VERSION 5.7 ;
  NOWIREEXTENSIONATPIN ON ;
  DIVIDERCHAR "/" ;
  BUSBITCHARS "[]" ;
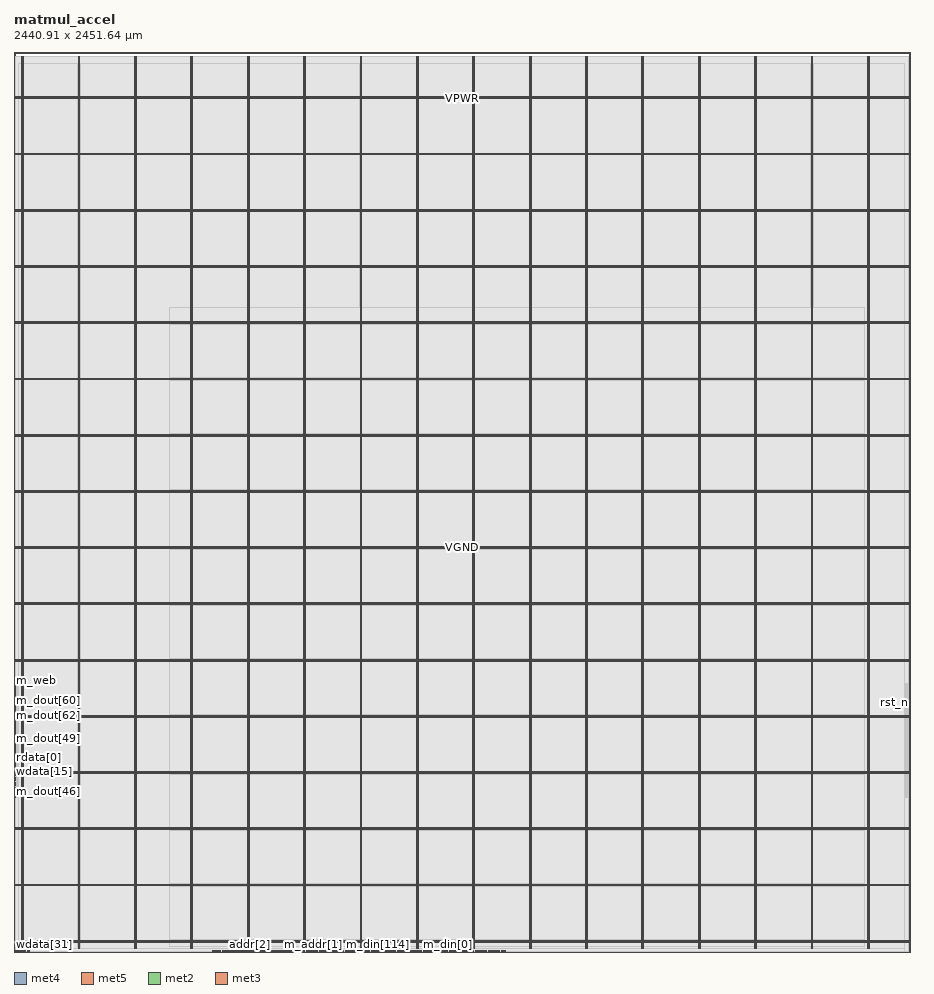
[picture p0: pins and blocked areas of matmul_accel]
MACRO matmul_accel
  CLASS BLOCK ;
  FOREIGN matmul_accel ;
  ORIGIN 0.000 0.000 ;
  SIZE 2440.915 BY 2451.635 ;
  PIN VGND
    DIRECTION INOUT ;
    USE GROUND ;
    PORT
      LAYER met4 ;
        RECT 24.340 10.640 25.940 2440.080 ;
    END
    PORT
      LAYER met4 ;
        RECT 177.940 10.640 179.540 2440.080 ;
    END
    PORT
      LAYER met4 ;
        RECT 331.540 10.640 333.140 2440.080 ;
    END
    PORT
      LAYER met4 ;
        RECT 485.140 10.640 486.740 2440.080 ;
    END
    PORT
      LAYER met4 ;
        RECT 638.740 10.640 640.340 2440.080 ;
    END
    PORT
      LAYER met4 ;
        RECT 792.340 10.640 793.940 2440.080 ;
    END
    PORT
      LAYER met4 ;
        RECT 945.940 10.640 947.540 2440.080 ;
    END
    PORT
      LAYER met4 ;
        RECT 1099.540 10.640 1101.140 2440.080 ;
    END
    PORT
      LAYER met4 ;
        RECT 1253.140 10.640 1254.740 2440.080 ;
    END
    PORT
      LAYER met4 ;
        RECT 1406.740 10.640 1408.340 2440.080 ;
    END
    PORT
      LAYER met4 ;
        RECT 1560.340 10.640 1561.940 2440.080 ;
    END
    PORT
      LAYER met4 ;
        RECT 1713.940 10.640 1715.540 2440.080 ;
    END
    PORT
      LAYER met4 ;
        RECT 1867.540 10.640 1869.140 2440.080 ;
    END
    PORT
      LAYER met4 ;
        RECT 2021.140 10.640 2022.740 2440.080 ;
    END
    PORT
      LAYER met4 ;
        RECT 2174.740 10.640 2176.340 2440.080 ;
    END
    PORT
      LAYER met4 ;
        RECT 2328.340 10.640 2329.940 2440.080 ;
    END
    PORT
      LAYER met5 ;
        RECT 5.280 30.030 2435.480 31.630 ;
    END
    PORT
      LAYER met5 ;
        RECT 5.280 183.210 2435.480 184.810 ;
    END
    PORT
      LAYER met5 ;
        RECT 5.280 336.390 2435.480 337.990 ;
    END
    PORT
      LAYER met5 ;
        RECT 5.280 489.570 2435.480 491.170 ;
    END
    PORT
      LAYER met5 ;
        RECT 5.280 642.750 2435.480 644.350 ;
    END
    PORT
      LAYER met5 ;
        RECT 5.280 795.930 2435.480 797.530 ;
    END
    PORT
      LAYER met5 ;
        RECT 5.280 949.110 2435.480 950.710 ;
    END
    PORT
      LAYER met5 ;
        RECT 5.280 1102.290 2435.480 1103.890 ;
    END
    PORT
      LAYER met5 ;
        RECT 5.280 1255.470 2435.480 1257.070 ;
    END
    PORT
      LAYER met5 ;
        RECT 5.280 1408.650 2435.480 1410.250 ;
    END
    PORT
      LAYER met5 ;
        RECT 5.280 1561.830 2435.480 1563.430 ;
    END
    PORT
      LAYER met5 ;
        RECT 5.280 1715.010 2435.480 1716.610 ;
    END
    PORT
      LAYER met5 ;
        RECT 5.280 1868.190 2435.480 1869.790 ;
    END
    PORT
      LAYER met5 ;
        RECT 5.280 2021.370 2435.480 2022.970 ;
    END
    PORT
      LAYER met5 ;
        RECT 5.280 2174.550 2435.480 2176.150 ;
    END
    PORT
      LAYER met5 ;
        RECT 5.280 2327.730 2435.480 2329.330 ;
    END
  END VGND
  PIN VPWR
    DIRECTION INOUT ;
    USE POWER ;
    PORT
      LAYER met4 ;
        RECT 21.040 10.640 22.640 2440.080 ;
    END
    PORT
      LAYER met4 ;
        RECT 174.640 10.640 176.240 2440.080 ;
    END
    PORT
      LAYER met4 ;
        RECT 328.240 10.640 329.840 2440.080 ;
    END
    PORT
      LAYER met4 ;
        RECT 481.840 10.640 483.440 2440.080 ;
    END
    PORT
      LAYER met4 ;
        RECT 635.440 10.640 637.040 2440.080 ;
    END
    PORT
      LAYER met4 ;
        RECT 789.040 10.640 790.640 2440.080 ;
    END
    PORT
      LAYER met4 ;
        RECT 942.640 10.640 944.240 2440.080 ;
    END
    PORT
      LAYER met4 ;
        RECT 1096.240 10.640 1097.840 2440.080 ;
    END
    PORT
      LAYER met4 ;
        RECT 1249.840 10.640 1251.440 2440.080 ;
    END
    PORT
      LAYER met4 ;
        RECT 1403.440 10.640 1405.040 2440.080 ;
    END
    PORT
      LAYER met4 ;
        RECT 1557.040 10.640 1558.640 2440.080 ;
    END
    PORT
      LAYER met4 ;
        RECT 1710.640 10.640 1712.240 2440.080 ;
    END
    PORT
      LAYER met4 ;
        RECT 1864.240 10.640 1865.840 2440.080 ;
    END
    PORT
      LAYER met4 ;
        RECT 2017.840 10.640 2019.440 2440.080 ;
    END
    PORT
      LAYER met4 ;
        RECT 2171.440 10.640 2173.040 2440.080 ;
    END
    PORT
      LAYER met4 ;
        RECT 2325.040 10.640 2326.640 2440.080 ;
    END
    PORT
      LAYER met5 ;
        RECT 5.280 26.730 2435.480 28.330 ;
    END
    PORT
      LAYER met5 ;
        RECT 5.280 179.910 2435.480 181.510 ;
    END
    PORT
      LAYER met5 ;
        RECT 5.280 333.090 2435.480 334.690 ;
    END
    PORT
      LAYER met5 ;
        RECT 5.280 486.270 2435.480 487.870 ;
    END
    PORT
      LAYER met5 ;
        RECT 5.280 639.450 2435.480 641.050 ;
    END
    PORT
      LAYER met5 ;
        RECT 5.280 792.630 2435.480 794.230 ;
    END
    PORT
      LAYER met5 ;
        RECT 5.280 945.810 2435.480 947.410 ;
    END
    PORT
      LAYER met5 ;
        RECT 5.280 1098.990 2435.480 1100.590 ;
    END
    PORT
      LAYER met5 ;
        RECT 5.280 1252.170 2435.480 1253.770 ;
    END
    PORT
      LAYER met5 ;
        RECT 5.280 1405.350 2435.480 1406.950 ;
    END
    PORT
      LAYER met5 ;
        RECT 5.280 1558.530 2435.480 1560.130 ;
    END
    PORT
      LAYER met5 ;
        RECT 5.280 1711.710 2435.480 1713.310 ;
    END
    PORT
      LAYER met5 ;
        RECT 5.280 1864.890 2435.480 1866.490 ;
    END
    PORT
      LAYER met5 ;
        RECT 5.280 2018.070 2435.480 2019.670 ;
    END
    PORT
      LAYER met5 ;
        RECT 5.280 2171.250 2435.480 2172.850 ;
    END
    PORT
      LAYER met5 ;
        RECT 5.280 2324.430 2435.480 2326.030 ;
    END
  END VPWR
  PIN addr[0]
    DIRECTION INPUT ;
    USE SIGNAL ;
    PORT
      LAYER met2 ;
        RECT 0.090 0.000 0.370 4.000 ;
    END
  END addr[0]
  PIN addr[10]
    DIRECTION INPUT ;
    USE SIGNAL ;
    ANTENNAGATEAREA 0.929700 ;
    ANTENNADIFFAREA 0.434700 ;
    PORT
      LAYER met2 ;
        RECT 676.290 0.000 676.570 4.000 ;
    END
  END addr[10]
  PIN addr[11]
    DIRECTION INPUT ;
    USE SIGNAL ;
    ANTENNAGATEAREA 0.860700 ;
    ANTENNADIFFAREA 0.434700 ;
    PORT
      LAYER met3 ;
        RECT 0.000 731.040 4.000 731.640 ;
    END
  END addr[11]
  PIN addr[12]
    DIRECTION INPUT ;
    USE SIGNAL ;
    ANTENNAGATEAREA 0.860700 ;
    ANTENNADIFFAREA 0.434700 ;
    PORT
      LAYER met3 ;
        RECT 0.000 669.840 4.000 670.440 ;
    END
  END addr[12]
  PIN addr[1]
    DIRECTION INPUT ;
    USE SIGNAL ;
    PORT
      LAYER met2 ;
        RECT 3.310 0.000 3.590 4.000 ;
    END
  END addr[1]
  PIN addr[2]
    DIRECTION INPUT ;
    USE SIGNAL ;
    ANTENNAGATEAREA 0.860700 ;
    ANTENNADIFFAREA 0.434700 ;
    PORT
      LAYER met2 ;
        RECT 644.090 0.000 644.370 4.000 ;
    END
  END addr[2]
  PIN addr[3]
    DIRECTION INPUT ;
    USE SIGNAL ;
    ANTENNAGATEAREA 0.860700 ;
    ANTENNADIFFAREA 0.434700 ;
    PORT
      LAYER met2 ;
        RECT 682.730 0.000 683.010 4.000 ;
    END
  END addr[3]
  PIN addr[4]
    DIRECTION INPUT ;
    USE SIGNAL ;
    ANTENNAGATEAREA 0.682200 ;
    ANTENNADIFFAREA 0.434700 ;
    PORT
      LAYER met2 ;
        RECT 673.070 0.000 673.350 4.000 ;
    END
  END addr[4]
  PIN addr[5]
    DIRECTION INPUT ;
    USE SIGNAL ;
    ANTENNAGATEAREA 0.682200 ;
    ANTENNADIFFAREA 0.434700 ;
    PORT
      LAYER met2 ;
        RECT 663.410 0.000 663.690 4.000 ;
    END
  END addr[5]
  PIN addr[6]
    DIRECTION INPUT ;
    USE SIGNAL ;
    ANTENNAGATEAREA 0.860700 ;
    ANTENNADIFFAREA 0.434700 ;
    PORT
      LAYER met3 ;
        RECT 0.000 663.040 4.000 663.640 ;
    END
  END addr[6]
  PIN addr[7]
    DIRECTION INPUT ;
    USE SIGNAL ;
    ANTENNAGATEAREA 0.682200 ;
    ANTENNADIFFAREA 0.434700 ;
    PORT
      LAYER met3 ;
        RECT 0.000 656.240 4.000 656.840 ;
    END
  END addr[7]
  PIN addr[8]
    DIRECTION INPUT ;
    USE SIGNAL ;
    ANTENNAGATEAREA 0.860700 ;
    ANTENNADIFFAREA 0.434700 ;
    PORT
      LAYER met3 ;
        RECT 0.000 659.640 4.000 660.240 ;
    END
  END addr[8]
  PIN addr[9]
    DIRECTION INPUT ;
    USE SIGNAL ;
    ANTENNAGATEAREA 0.860700 ;
    ANTENNADIFFAREA 0.434700 ;
    PORT
      LAYER met3 ;
        RECT 0.000 601.840 4.000 602.440 ;
    END
  END addr[9]
  PIN busy
    DIRECTION OUTPUT ;
    USE SIGNAL ;
    ANTENNADIFFAREA 0.445500 ;
    PORT
      LAYER met2 ;
        RECT 708.490 0.000 708.770 4.000 ;
    END
  END busy
  PIN clk
    DIRECTION INPUT ;
    USE SIGNAL ;
    ANTENNAGATEAREA 1.286700 ;
    ANTENNADIFFAREA 0.434700 ;
    PORT
      LAYER met2 ;
        RECT 25.850 0.000 26.130 4.000 ;
    END
  END clk
  PIN done
    DIRECTION OUTPUT ;
    USE SIGNAL ;
    ANTENNADIFFAREA 0.445500 ;
    PORT
      LAYER met2 ;
        RECT 711.710 0.000 711.990 4.000 ;
    END
  END done
  PIN m_addr[0]
    DIRECTION OUTPUT ;
    USE SIGNAL ;
    ANTENNADIFFAREA 0.445500 ;
    PORT
      LAYER met2 ;
        RECT 782.550 0.000 782.830 4.000 ;
    END
  END m_addr[0]
  PIN m_addr[10]
    DIRECTION OUTPUT ;
    USE SIGNAL ;
    ANTENNADIFFAREA 0.445500 ;
    PORT
      LAYER met2 ;
        RECT 756.790 0.000 757.070 4.000 ;
    END
  END m_addr[10]
  PIN m_addr[11]
    DIRECTION OUTPUT ;
    USE SIGNAL ;
    ANTENNADIFFAREA 0.445500 ;
    PORT
      LAYER met2 ;
        RECT 750.350 0.000 750.630 4.000 ;
    END
  END m_addr[11]
  PIN m_addr[12]
    DIRECTION OUTPUT ;
    USE SIGNAL ;
    ANTENNADIFFAREA 0.445500 ;
    PORT
      LAYER met2 ;
        RECT 763.230 0.000 763.510 4.000 ;
    END
  END m_addr[12]
  PIN m_addr[13]
    DIRECTION OUTPUT ;
    USE SIGNAL ;
    ANTENNADIFFAREA 0.445500 ;
    PORT
      LAYER met2 ;
        RECT 760.010 0.000 760.290 4.000 ;
    END
  END m_addr[13]
  PIN m_addr[1]
    DIRECTION OUTPUT ;
    USE SIGNAL ;
    ANTENNADIFFAREA 0.445500 ;
    PORT
      LAYER met2 ;
        RECT 814.750 0.000 815.030 4.000 ;
    END
  END m_addr[1]
  PIN m_addr[2]
    DIRECTION OUTPUT ;
    USE SIGNAL ;
    ANTENNADIFFAREA 0.445500 ;
    PORT
      LAYER met2 ;
        RECT 817.970 0.000 818.250 4.000 ;
    END
  END m_addr[2]
  PIN m_addr[3]
    DIRECTION OUTPUT ;
    USE SIGNAL ;
    ANTENNADIFFAREA 0.445500 ;
    PORT
      LAYER met2 ;
        RECT 811.530 0.000 811.810 4.000 ;
    END
  END m_addr[3]
  PIN m_addr[4]
    DIRECTION OUTPUT ;
    USE SIGNAL ;
    ANTENNADIFFAREA 0.445500 ;
    PORT
      LAYER met2 ;
        RECT 753.570 0.000 753.850 4.000 ;
    END
  END m_addr[4]
  PIN m_addr[5]
    DIRECTION OUTPUT ;
    USE SIGNAL ;
    ANTENNADIFFAREA 0.445500 ;
    PORT
      LAYER met2 ;
        RECT 801.870 0.000 802.150 4.000 ;
    END
  END m_addr[5]
  PIN m_addr[6]
    DIRECTION OUTPUT ;
    USE SIGNAL ;
    ANTENNADIFFAREA 0.445500 ;
    PORT
      LAYER met2 ;
        RECT 766.450 0.000 766.730 4.000 ;
    END
  END m_addr[6]
  PIN m_addr[7]
    DIRECTION OUTPUT ;
    USE SIGNAL ;
    ANTENNADIFFAREA 0.445500 ;
    PORT
      LAYER met2 ;
        RECT 747.130 0.000 747.410 4.000 ;
    END
  END m_addr[7]
  PIN m_addr[8]
    DIRECTION OUTPUT ;
    USE SIGNAL ;
    ANTENNADIFFAREA 0.445500 ;
    PORT
      LAYER met2 ;
        RECT 740.690 0.000 740.970 4.000 ;
    END
  END m_addr[8]
  PIN m_addr[9]
    DIRECTION OUTPUT ;
    USE SIGNAL ;
    ANTENNADIFFAREA 0.445500 ;
    PORT
      LAYER met2 ;
        RECT 772.890 0.000 773.170 4.000 ;
    END
  END m_addr[9]
  PIN m_csb
    DIRECTION OUTPUT ;
    USE SIGNAL ;
    ANTENNADIFFAREA 0.445500 ;
    PORT
      LAYER met2 ;
        RECT 724.590 0.000 724.870 4.000 ;
    END
  END m_csb
  PIN m_din[0]
    DIRECTION OUTPUT ;
    USE SIGNAL ;
    ANTENNADIFFAREA 0.445500 ;
    PORT
      LAYER met2 ;
        RECT 1181.830 0.000 1182.110 4.000 ;
    END
  END m_din[0]
  PIN m_din[100]
    DIRECTION OUTPUT ;
    USE SIGNAL ;
    ANTENNADIFFAREA 0.445500 ;
    PORT
      LAYER met2 ;
        RECT 859.830 0.000 860.110 4.000 ;
    END
  END m_din[100]
  PIN m_din[101]
    DIRECTION OUTPUT ;
    USE SIGNAL ;
    ANTENNADIFFAREA 0.445500 ;
    PORT
      LAYER met2 ;
        RECT 1175.390 0.000 1175.670 4.000 ;
    END
  END m_din[101]
  PIN m_din[102]
    DIRECTION OUTPUT ;
    USE SIGNAL ;
    ANTENNADIFFAREA 0.445500 ;
    PORT
      LAYER met2 ;
        RECT 863.050 0.000 863.330 4.000 ;
    END
  END m_din[102]
  PIN m_din[103]
    DIRECTION OUTPUT ;
    USE SIGNAL ;
    ANTENNADIFFAREA 0.445500 ;
    PORT
      LAYER met2 ;
        RECT 1024.050 0.000 1024.330 4.000 ;
    END
  END m_din[103]
  PIN m_din[104]
    DIRECTION OUTPUT ;
    USE SIGNAL ;
    ANTENNADIFFAREA 0.445500 ;
    PORT
      LAYER met2 ;
        RECT 689.170 0.000 689.450 4.000 ;
    END
  END m_din[104]
  PIN m_din[105]
    DIRECTION OUTPUT ;
    USE SIGNAL ;
    ANTENNADIFFAREA 0.445500 ;
    PORT
      LAYER met2 ;
        RECT 1130.310 0.000 1130.590 4.000 ;
    END
  END m_din[105]
  PIN m_din[106]
    DIRECTION OUTPUT ;
    USE SIGNAL ;
    ANTENNADIFFAREA 0.445500 ;
    PORT
      LAYER met2 ;
        RECT 731.030 0.000 731.310 4.000 ;
    END
  END m_din[106]
  PIN m_din[107]
    DIRECTION OUTPUT ;
    USE SIGNAL ;
    ANTENNADIFFAREA 0.445500 ;
    PORT
      LAYER met2 ;
        RECT 743.910 0.000 744.190 4.000 ;
    END
  END m_din[107]
  PIN m_din[108]
    DIRECTION OUTPUT ;
    USE SIGNAL ;
    ANTENNADIFFAREA 0.445500 ;
    PORT
      LAYER met2 ;
        RECT 1236.570 0.000 1236.850 4.000 ;
    END
  END m_din[108]
  PIN m_din[109]
    DIRECTION OUTPUT ;
    USE SIGNAL ;
    ANTENNADIFFAREA 0.445500 ;
    PORT
      LAYER met2 ;
        RECT 830.850 0.000 831.130 4.000 ;
    END
  END m_din[109]
  PIN m_din[10]
    DIRECTION OUTPUT ;
    USE SIGNAL ;
    ANTENNADIFFAREA 0.445500 ;
    PORT
      LAYER met2 ;
        RECT 714.930 0.000 715.210 4.000 ;
    END
  END m_din[10]
  PIN m_din[110]
    DIRECTION OUTPUT ;
    USE SIGNAL ;
    ANTENNADIFFAREA 0.445500 ;
    PORT
      LAYER met2 ;
        RECT 882.370 0.000 882.650 4.000 ;
    END
  END m_din[110]
  PIN m_din[111]
    DIRECTION OUTPUT ;
    USE SIGNAL ;
    ANTENNADIFFAREA 0.445500 ;
    PORT
      LAYER met2 ;
        RECT 779.330 0.000 779.610 4.000 ;
    END
  END m_din[111]
  PIN m_din[112]
    DIRECTION OUTPUT ;
    USE SIGNAL ;
    ANTENNADIFFAREA 0.445500 ;
    PORT
      LAYER met2 ;
        RECT 647.310 0.000 647.590 4.000 ;
    END
  END m_din[112]
  PIN m_din[113]
    DIRECTION OUTPUT ;
    USE SIGNAL ;
    ANTENNADIFFAREA 0.445500 ;
    PORT
      LAYER met2 ;
        RECT 914.570 0.000 914.850 4.000 ;
    END
  END m_din[113]
  PIN m_din[114]
    DIRECTION OUTPUT ;
    USE SIGNAL ;
    ANTENNADIFFAREA 0.445500 ;
    PORT
      LAYER met2 ;
        RECT 991.850 0.000 992.130 4.000 ;
    END
  END m_din[114]
  PIN m_din[115]
    DIRECTION OUTPUT ;
    USE SIGNAL ;
    ANTENNADIFFAREA 0.445500 ;
    PORT
      LAYER met2 ;
        RECT 669.850 0.000 670.130 4.000 ;
    END
  END m_din[115]
  PIN m_din[116]
    DIRECTION OUTPUT ;
    USE SIGNAL ;
    ANTENNADIFFAREA 0.445500 ;
    PORT
      LAYER met2 ;
        RECT 718.150 0.000 718.430 4.000 ;
    END
  END m_din[116]
  PIN m_din[117]
    DIRECTION OUTPUT ;
    USE SIGNAL ;
    ANTENNADIFFAREA 0.445500 ;
    PORT
      LAYER met2 ;
        RECT 888.810 0.000 889.090 4.000 ;
    END
  END m_din[117]
  PIN m_din[118]
    DIRECTION OUTPUT ;
    USE SIGNAL ;
    ANTENNADIFFAREA 0.445500 ;
    PORT
      LAYER met2 ;
        RECT 1281.650 0.000 1281.930 4.000 ;
    END
  END m_din[118]
  PIN m_din[119]
    DIRECTION OUTPUT ;
    USE SIGNAL ;
    ANTENNADIFFAREA 0.445500 ;
    PORT
      LAYER met2 ;
        RECT 792.210 0.000 792.490 4.000 ;
    END
  END m_din[119]
  PIN m_din[11]
    DIRECTION OUTPUT ;
    USE SIGNAL ;
    ANTENNADIFFAREA 0.445500 ;
    PORT
      LAYER met2 ;
        RECT 885.590 0.000 885.870 4.000 ;
    END
  END m_din[11]
  PIN m_din[120]
    DIRECTION OUTPUT ;
    USE SIGNAL ;
    ANTENNADIFFAREA 0.445500 ;
    PORT
      LAYER met2 ;
        RECT 927.450 0.000 927.730 4.000 ;
    END
  END m_din[120]
  PIN m_din[121]
    DIRECTION OUTPUT ;
    USE SIGNAL ;
    ANTENNADIFFAREA 0.445500 ;
    PORT
      LAYER met2 ;
        RECT 666.630 0.000 666.910 4.000 ;
    END
  END m_din[121]
  PIN m_din[122]
    DIRECTION OUTPUT ;
    USE SIGNAL ;
    ANTENNADIFFAREA 0.445500 ;
    PORT
      LAYER met2 ;
        RECT 679.510 0.000 679.790 4.000 ;
    END
  END m_din[122]
  PIN m_din[123]
    DIRECTION OUTPUT ;
    USE SIGNAL ;
    ANTENNADIFFAREA 0.445500 ;
    PORT
      LAYER met2 ;
        RECT 1117.430 0.000 1117.710 4.000 ;
    END
  END m_din[123]
  PIN m_din[124]
    DIRECTION OUTPUT ;
    USE SIGNAL ;
    ANTENNADIFFAREA 0.445500 ;
    PORT
      LAYER met2 ;
        RECT 695.610 0.000 695.890 4.000 ;
    END
  END m_din[124]
  PIN m_din[125]
    DIRECTION OUTPUT ;
    USE SIGNAL ;
    ANTENNADIFFAREA 0.445500 ;
    PORT
      LAYER met2 ;
        RECT 901.690 0.000 901.970 4.000 ;
    END
  END m_din[125]
  PIN m_din[126]
    DIRECTION OUTPUT ;
    USE SIGNAL ;
    ANTENNADIFFAREA 0.445500 ;
    PORT
      LAYER met2 ;
        RECT 1014.390 0.000 1014.670 4.000 ;
    END
  END m_din[126]
  PIN m_din[127]
    DIRECTION OUTPUT ;
    USE SIGNAL ;
    ANTENNADIFFAREA 0.445500 ;
    PORT
      LAYER met2 ;
        RECT 1127.090 0.000 1127.370 4.000 ;
    END
  END m_din[127]
  PIN m_din[12]
    DIRECTION OUTPUT ;
    USE SIGNAL ;
    ANTENNADIFFAREA 0.445500 ;
    PORT
      LAYER met2 ;
        RECT 1133.530 0.000 1133.810 4.000 ;
    END
  END m_din[12]
  PIN m_din[13]
    DIRECTION OUTPUT ;
    USE SIGNAL ;
    ANTENNADIFFAREA 0.445500 ;
    PORT
      LAYER met2 ;
        RECT 834.070 0.000 834.350 4.000 ;
    END
  END m_din[13]
  PIN m_din[14]
    DIRECTION OUTPUT ;
    USE SIGNAL ;
    ANTENNADIFFAREA 0.445500 ;
    PORT
      LAYER met2 ;
        RECT 1252.670 0.000 1252.950 4.000 ;
    END
  END m_din[14]
  PIN m_din[15]
    DIRECTION OUTPUT ;
    USE SIGNAL ;
    ANTENNADIFFAREA 0.445500 ;
    PORT
      LAYER met2 ;
        RECT 1275.210 0.000 1275.490 4.000 ;
    END
  END m_din[15]
  PIN m_din[16]
    DIRECTION OUTPUT ;
    USE SIGNAL ;
    ANTENNADIFFAREA 0.445500 ;
    PORT
      LAYER met2 ;
        RECT 940.330 0.000 940.610 4.000 ;
    END
  END m_din[16]
  PIN m_din[17]
    DIRECTION OUTPUT ;
    USE SIGNAL ;
    ANTENNADIFFAREA 0.445500 ;
    PORT
      LAYER met2 ;
        RECT 1123.870 0.000 1124.150 4.000 ;
    END
  END m_din[17]
  PIN m_din[18]
    DIRECTION OUTPUT ;
    USE SIGNAL ;
    ANTENNADIFFAREA 0.445500 ;
    PORT
      LAYER met2 ;
        RECT 1065.910 0.000 1066.190 4.000 ;
    END
  END m_din[18]
  PIN m_din[19]
    DIRECTION OUTPUT ;
    USE SIGNAL ;
    ANTENNADIFFAREA 0.445500 ;
    PORT
      LAYER met2 ;
        RECT 1143.190 0.000 1143.470 4.000 ;
    END
  END m_din[19]
  PIN m_din[1]
    DIRECTION OUTPUT ;
    USE SIGNAL ;
    ANTENNADIFFAREA 0.445500 ;
    PORT
      LAYER met2 ;
        RECT 1059.470 0.000 1059.750 4.000 ;
    END
  END m_din[1]
  PIN m_din[20]
    DIRECTION OUTPUT ;
    USE SIGNAL ;
    ANTENNADIFFAREA 0.445500 ;
    PORT
      LAYER met2 ;
        RECT 1053.030 0.000 1053.310 4.000 ;
    END
  END m_din[20]
  PIN m_din[21]
    DIRECTION OUTPUT ;
    USE SIGNAL ;
    ANTENNADIFFAREA 0.445500 ;
    PORT
      LAYER met2 ;
        RECT 1259.110 0.000 1259.390 4.000 ;
    END
  END m_din[21]
  PIN m_din[22]
    DIRECTION OUTPUT ;
    USE SIGNAL ;
    ANTENNADIFFAREA 0.445500 ;
    PORT
      LAYER met2 ;
        RECT 1056.250 0.000 1056.530 4.000 ;
    END
  END m_din[22]
  PIN m_din[23]
    DIRECTION OUTPUT ;
    USE SIGNAL ;
    ANTENNADIFFAREA 0.445500 ;
    PORT
      LAYER met2 ;
        RECT 1156.070 0.000 1156.350 4.000 ;
    END
  END m_din[23]
  PIN m_din[24]
    DIRECTION OUTPUT ;
    USE SIGNAL ;
    ANTENNADIFFAREA 0.445500 ;
    PORT
      LAYER met2 ;
        RECT 1220.470 0.000 1220.750 4.000 ;
    END
  END m_din[24]
  PIN m_din[25]
    DIRECTION OUTPUT ;
    USE SIGNAL ;
    ANTENNADIFFAREA 0.445500 ;
    PORT
      LAYER met2 ;
        RECT 1001.510 0.000 1001.790 4.000 ;
    END
  END m_din[25]
  PIN m_din[26]
    DIRECTION OUTPUT ;
    USE SIGNAL ;
    ANTENNADIFFAREA 0.445500 ;
    PORT
      LAYER met2 ;
        RECT 1110.990 0.000 1111.270 4.000 ;
    END
  END m_din[26]
  PIN m_din[27]
    DIRECTION OUTPUT ;
    USE SIGNAL ;
    ANTENNADIFFAREA 0.445500 ;
    PORT
      LAYER met2 ;
        RECT 1239.790 0.000 1240.070 4.000 ;
    END
  END m_din[27]
  PIN m_din[28]
    DIRECTION OUTPUT ;
    USE SIGNAL ;
    ANTENNADIFFAREA 0.445500 ;
    PORT
      LAYER met2 ;
        RECT 1217.250 0.000 1217.530 4.000 ;
    END
  END m_din[28]
  PIN m_din[29]
    DIRECTION OUTPUT ;
    USE SIGNAL ;
    ANTENNADIFFAREA 0.445500 ;
    PORT
      LAYER met2 ;
        RECT 1207.590 0.000 1207.870 4.000 ;
    END
  END m_din[29]
  PIN m_din[2]
    DIRECTION OUTPUT ;
    USE SIGNAL ;
    ANTENNADIFFAREA 0.445500 ;
    PORT
      LAYER met2 ;
        RECT 1094.890 0.000 1095.170 4.000 ;
    END
  END m_din[2]
  PIN m_din[30]
    DIRECTION OUTPUT ;
    USE SIGNAL ;
    ANTENNADIFFAREA 0.445500 ;
    PORT
      LAYER met2 ;
        RECT 1004.730 0.000 1005.010 4.000 ;
    END
  END m_din[30]
  PIN m_din[31]
    DIRECTION OUTPUT ;
    USE SIGNAL ;
    ANTENNADIFFAREA 0.445500 ;
    PORT
      LAYER met2 ;
        RECT 1246.230 0.000 1246.510 4.000 ;
    END
  END m_din[31]
  PIN m_din[32]
    DIRECTION OUTPUT ;
    USE SIGNAL ;
    ANTENNADIFFAREA 0.445500 ;
    PORT
      LAYER met2 ;
        RECT 962.870 0.000 963.150 4.000 ;
    END
  END m_din[32]
  PIN m_din[33]
    DIRECTION OUTPUT ;
    USE SIGNAL ;
    ANTENNADIFFAREA 0.445500 ;
    PORT
      LAYER met2 ;
        RECT 1017.610 0.000 1017.890 4.000 ;
    END
  END m_din[33]
  PIN m_din[34]
    DIRECTION OUTPUT ;
    USE SIGNAL ;
    ANTENNADIFFAREA 0.445500 ;
    PORT
      LAYER met2 ;
        RECT 1036.930 0.000 1037.210 4.000 ;
    END
  END m_din[34]
  PIN m_din[35]
    DIRECTION OUTPUT ;
    USE SIGNAL ;
    ANTENNADIFFAREA 0.445500 ;
    PORT
      LAYER met2 ;
        RECT 1168.950 0.000 1169.230 4.000 ;
    END
  END m_din[35]
  PIN m_din[36]
    DIRECTION OUTPUT ;
    USE SIGNAL ;
    ANTENNADIFFAREA 0.445500 ;
    PORT
      LAYER met2 ;
        RECT 856.610 0.000 856.890 4.000 ;
    END
  END m_din[36]
  PIN m_din[37]
    DIRECTION OUTPUT ;
    USE SIGNAL ;
    ANTENNADIFFAREA 0.445500 ;
    PORT
      LAYER met2 ;
        RECT 1159.290 0.000 1159.570 4.000 ;
    END
  END m_din[37]
  PIN m_din[38]
    DIRECTION OUTPUT ;
    USE SIGNAL ;
    ANTENNADIFFAREA 0.445500 ;
    PORT
      LAYER met2 ;
        RECT 837.290 0.000 837.570 4.000 ;
    END
  END m_din[38]
  PIN m_din[39]
    DIRECTION OUTPUT ;
    USE SIGNAL ;
    ANTENNADIFFAREA 0.445500 ;
    PORT
      LAYER met2 ;
        RECT 978.970 0.000 979.250 4.000 ;
    END
  END m_din[39]
  PIN m_din[3]
    DIRECTION OUTPUT ;
    USE SIGNAL ;
    ANTENNADIFFAREA 0.445500 ;
    PORT
      LAYER met2 ;
        RECT 953.210 0.000 953.490 4.000 ;
    END
  END m_din[3]
  PIN m_din[40]
    DIRECTION OUTPUT ;
    USE SIGNAL ;
    ANTENNADIFFAREA 0.445500 ;
    PORT
      LAYER met2 ;
        RECT 769.670 0.000 769.950 4.000 ;
    END
  END m_din[40]
  PIN m_din[41]
    DIRECTION OUTPUT ;
    USE SIGNAL ;
    ANTENNADIFFAREA 0.445500 ;
    PORT
      LAYER met2 ;
        RECT 1107.770 0.000 1108.050 4.000 ;
    END
  END m_din[41]
  PIN m_din[42]
    DIRECTION OUTPUT ;
    USE SIGNAL ;
    ANTENNADIFFAREA 0.445500 ;
    PORT
      LAYER met2 ;
        RECT 776.110 0.000 776.390 4.000 ;
    END
  END m_din[42]
  PIN m_din[43]
    DIRECTION OUTPUT ;
    USE SIGNAL ;
    ANTENNADIFFAREA 0.445500 ;
    PORT
      LAYER met2 ;
        RECT 685.950 0.000 686.230 4.000 ;
    END
  END m_din[43]
  PIN m_din[44]
    DIRECTION OUTPUT ;
    USE SIGNAL ;
    ANTENNADIFFAREA 0.445500 ;
    PORT
      LAYER met2 ;
        RECT 1197.930 0.000 1198.210 4.000 ;
    END
  END m_din[44]
  PIN m_din[45]
    DIRECTION OUTPUT ;
    USE SIGNAL ;
    ANTENNADIFFAREA 0.445500 ;
    PORT
      LAYER met2 ;
        RECT 827.630 0.000 827.910 4.000 ;
    END
  END m_din[45]
  PIN m_din[46]
    DIRECTION OUTPUT ;
    USE SIGNAL ;
    ANTENNADIFFAREA 0.445500 ;
    PORT
      LAYER met2 ;
        RECT 805.090 0.000 805.370 4.000 ;
    END
  END m_din[46]
  PIN m_din[47]
    DIRECTION OUTPUT ;
    USE SIGNAL ;
    ANTENNADIFFAREA 0.445500 ;
    PORT
      LAYER met2 ;
        RECT 788.990 0.000 789.270 4.000 ;
    END
  END m_din[47]
  PIN m_din[48]
    DIRECTION OUTPUT ;
    USE SIGNAL ;
    ANTENNADIFFAREA 0.445500 ;
    PORT
      LAYER met2 ;
        RECT 1194.710 0.000 1194.990 4.000 ;
    END
  END m_din[48]
  PIN m_din[49]
    DIRECTION OUTPUT ;
    USE SIGNAL ;
    ANTENNADIFFAREA 0.445500 ;
    PORT
      LAYER met2 ;
        RECT 956.430 0.000 956.710 4.000 ;
    END
  END m_din[49]
  PIN m_din[4]
    DIRECTION OUTPUT ;
    USE SIGNAL ;
    ANTENNADIFFAREA 0.445500 ;
    PORT
      LAYER met2 ;
        RECT 821.190 0.000 821.470 4.000 ;
    END
  END m_din[4]
  PIN m_din[50]
    DIRECTION OUTPUT ;
    USE SIGNAL ;
    ANTENNADIFFAREA 0.445500 ;
    PORT
      LAYER met2 ;
        RECT 1230.130 0.000 1230.410 4.000 ;
    END
  END m_din[50]
  PIN m_din[51]
    DIRECTION OUTPUT ;
    USE SIGNAL ;
    ANTENNADIFFAREA 0.445500 ;
    PORT
      LAYER met2 ;
        RECT 1020.830 0.000 1021.110 4.000 ;
    END
  END m_din[51]
  PIN m_din[52]
    DIRECTION OUTPUT ;
    USE SIGNAL ;
    ANTENNADIFFAREA 0.445500 ;
    PORT
      LAYER met2 ;
        RECT 1085.230 0.000 1085.510 4.000 ;
    END
  END m_din[52]
  PIN m_din[53]
    DIRECTION OUTPUT ;
    USE SIGNAL ;
    ANTENNADIFFAREA 0.445500 ;
    PORT
      LAYER met2 ;
        RECT 982.190 0.000 982.470 4.000 ;
    END
  END m_din[53]
  PIN m_din[54]
    DIRECTION OUTPUT ;
    USE SIGNAL ;
    ANTENNADIFFAREA 0.445500 ;
    PORT
      LAYER met2 ;
        RECT 988.630 0.000 988.910 4.000 ;
    END
  END m_din[54]
  PIN m_din[55]
    DIRECTION OUTPUT ;
    USE SIGNAL ;
    ANTENNADIFFAREA 0.445500 ;
    PORT
      LAYER met2 ;
        RECT 1262.330 0.000 1262.610 4.000 ;
    END
  END m_din[55]
  PIN m_din[56]
    DIRECTION OUTPUT ;
    USE SIGNAL ;
    ANTENNADIFFAREA 0.445500 ;
    PORT
      LAYER met2 ;
        RECT 1091.670 0.000 1091.950 4.000 ;
    END
  END m_din[56]
  PIN m_din[57]
    DIRECTION OUTPUT ;
    USE SIGNAL ;
    ANTENNADIFFAREA 0.445500 ;
    PORT
      LAYER met2 ;
        RECT 1191.490 0.000 1191.770 4.000 ;
    END
  END m_din[57]
  PIN m_din[58]
    DIRECTION OUTPUT ;
    USE SIGNAL ;
    ANTENNADIFFAREA 0.445500 ;
    PORT
      LAYER met2 ;
        RECT 1284.870 0.000 1285.150 4.000 ;
    END
  END m_din[58]
  PIN m_din[59]
    DIRECTION OUTPUT ;
    USE SIGNAL ;
    ANTENNADIFFAREA 0.445500 ;
    PORT
      LAYER met2 ;
        RECT 972.530 0.000 972.810 4.000 ;
    END
  END m_din[59]
  PIN m_din[5]
    DIRECTION OUTPUT ;
    USE SIGNAL ;
    ANTENNADIFFAREA 0.445500 ;
    PORT
      LAYER met2 ;
        RECT 1049.810 0.000 1050.090 4.000 ;
    END
  END m_din[5]
  PIN m_din[60]
    DIRECTION OUTPUT ;
    USE SIGNAL ;
    ANTENNADIFFAREA 0.445500 ;
    PORT
      LAYER met2 ;
        RECT 1201.150 0.000 1201.430 4.000 ;
    END
  END m_din[60]
  PIN m_din[61]
    DIRECTION OUTPUT ;
    USE SIGNAL ;
    ANTENNADIFFAREA 0.445500 ;
    PORT
      LAYER met2 ;
        RECT 1027.270 0.000 1027.550 4.000 ;
    END
  END m_din[61]
  PIN m_din[62]
    DIRECTION OUTPUT ;
    USE SIGNAL ;
    ANTENNADIFFAREA 0.445500 ;
    PORT
      LAYER met2 ;
        RECT 933.890 0.000 934.170 4.000 ;
    END
  END m_din[62]
  PIN m_din[63]
    DIRECTION OUTPUT ;
    USE SIGNAL ;
    ANTENNADIFFAREA 0.445500 ;
    PORT
      LAYER met2 ;
        RECT 975.750 0.000 976.030 4.000 ;
    END
  END m_din[63]
  PIN m_din[64]
    DIRECTION OUTPUT ;
    USE SIGNAL ;
    ANTENNADIFFAREA 0.445500 ;
    PORT
      LAYER met2 ;
        RECT 1120.650 0.000 1120.930 4.000 ;
    END
  END m_din[64]
  PIN m_din[65]
    DIRECTION OUTPUT ;
    USE SIGNAL ;
    ANTENNADIFFAREA 0.445500 ;
    PORT
      LAYER met2 ;
        RECT 924.230 0.000 924.510 4.000 ;
    END
  END m_din[65]
  PIN m_din[66]
    DIRECTION OUTPUT ;
    USE SIGNAL ;
    ANTENNADIFFAREA 0.445500 ;
    PORT
      LAYER met2 ;
        RECT 1178.610 0.000 1178.890 4.000 ;
    END
  END m_din[66]
  PIN m_din[67]
    DIRECTION OUTPUT ;
    USE SIGNAL ;
    ANTENNADIFFAREA 0.445500 ;
    PORT
      LAYER met2 ;
        RECT 985.410 0.000 985.690 4.000 ;
    END
  END m_din[67]
  PIN m_din[68]
    DIRECTION OUTPUT ;
    USE SIGNAL ;
    ANTENNADIFFAREA 0.445500 ;
    PORT
      LAYER met2 ;
        RECT 840.510 0.000 840.790 4.000 ;
    END
  END m_din[68]
  PIN m_din[69]
    DIRECTION OUTPUT ;
    USE SIGNAL ;
    ANTENNADIFFAREA 0.445500 ;
    PORT
      LAYER met2 ;
        RECT 921.010 0.000 921.290 4.000 ;
    END
  END m_din[69]
  PIN m_din[6]
    DIRECTION OUTPUT ;
    USE SIGNAL ;
    ANTENNADIFFAREA 0.445500 ;
    PORT
      LAYER met2 ;
        RECT 869.490 0.000 869.770 4.000 ;
    END
  END m_din[6]
  PIN m_din[70]
    DIRECTION OUTPUT ;
    USE SIGNAL ;
    ANTENNADIFFAREA 0.445500 ;
    PORT
      LAYER met2 ;
        RECT 866.270 0.000 866.550 4.000 ;
    END
  END m_din[70]
  PIN m_din[71]
    DIRECTION OUTPUT ;
    USE SIGNAL ;
    ANTENNADIFFAREA 0.445500 ;
    PORT
      LAYER met2 ;
        RECT 966.090 0.000 966.370 4.000 ;
    END
  END m_din[71]
  PIN m_din[72]
    DIRECTION OUTPUT ;
    USE SIGNAL ;
    ANTENNADIFFAREA 0.445500 ;
    PORT
      LAYER met2 ;
        RECT 705.270 0.000 705.550 4.000 ;
    END
  END m_din[72]
  PIN m_din[73]
    DIRECTION OUTPUT ;
    USE SIGNAL ;
    ANTENNADIFFAREA 0.445500 ;
    PORT
      LAYER met2 ;
        RECT 1249.450 0.000 1249.730 4.000 ;
    END
  END m_din[73]
  PIN m_din[74]
    DIRECTION OUTPUT ;
    USE SIGNAL ;
    ANTENNADIFFAREA 0.445500 ;
    PORT
      LAYER met2 ;
        RECT 798.650 0.000 798.930 4.000 ;
    END
  END m_din[74]
  PIN m_din[75]
    DIRECTION OUTPUT ;
    USE SIGNAL ;
    ANTENNADIFFAREA 0.445500 ;
    PORT
      LAYER met2 ;
        RECT 727.810 0.000 728.090 4.000 ;
    END
  END m_din[75]
  PIN m_din[76]
    DIRECTION OUTPUT ;
    USE SIGNAL ;
    ANTENNADIFFAREA 0.445500 ;
    PORT
      LAYER met2 ;
        RECT 1136.750 0.000 1137.030 4.000 ;
    END
  END m_din[76]
  PIN m_din[77]
    DIRECTION OUTPUT ;
    USE SIGNAL ;
    ANTENNADIFFAREA 0.445500 ;
    PORT
      LAYER met2 ;
        RECT 850.170 0.000 850.450 4.000 ;
    END
  END m_din[77]
  PIN m_din[78]
    DIRECTION OUTPUT ;
    USE SIGNAL ;
    ANTENNADIFFAREA 0.445500 ;
    PORT
      LAYER met2 ;
        RECT 1011.170 0.000 1011.450 4.000 ;
    END
  END m_din[78]
  PIN m_din[79]
    DIRECTION OUTPUT ;
    USE SIGNAL ;
    ANTENNADIFFAREA 0.445500 ;
    PORT
      LAYER met2 ;
        RECT 1043.370 0.000 1043.650 4.000 ;
    END
  END m_din[79]
  PIN m_din[7]
    DIRECTION OUTPUT ;
    USE SIGNAL ;
    ANTENNADIFFAREA 0.445500 ;
    PORT
      LAYER met2 ;
        RECT 1265.550 0.000 1265.830 4.000 ;
    END
  END m_din[7]
  PIN m_din[80]
    DIRECTION OUTPUT ;
    USE SIGNAL ;
    ANTENNADIFFAREA 0.445500 ;
    PORT
      LAYER met2 ;
        RECT 998.290 0.000 998.570 4.000 ;
    END
  END m_din[80]
  PIN m_din[81]
    DIRECTION OUTPUT ;
    USE SIGNAL ;
    ANTENNADIFFAREA 0.445500 ;
    PORT
      LAYER met2 ;
        RECT 1046.590 0.000 1046.870 4.000 ;
    END
  END m_din[81]
  PIN m_din[82]
    DIRECTION OUTPUT ;
    USE SIGNAL ;
    ANTENNADIFFAREA 0.445500 ;
    PORT
      LAYER met2 ;
        RECT 1233.350 0.000 1233.630 4.000 ;
    END
  END m_din[82]
  PIN m_din[83]
    DIRECTION OUTPUT ;
    USE SIGNAL ;
    ANTENNADIFFAREA 0.445500 ;
    PORT
      LAYER met2 ;
        RECT 1271.990 0.000 1272.270 4.000 ;
    END
  END m_din[83]
  PIN m_din[84]
    DIRECTION OUTPUT ;
    USE SIGNAL ;
    ANTENNADIFFAREA 0.445500 ;
    PORT
      LAYER met2 ;
        RECT 1082.010 0.000 1082.290 4.000 ;
    END
  END m_din[84]
  PIN m_din[85]
    DIRECTION OUTPUT ;
    USE SIGNAL ;
    ANTENNADIFFAREA 0.445500 ;
    PORT
      LAYER met2 ;
        RECT 1214.030 0.000 1214.310 4.000 ;
    END
  END m_din[85]
  PIN m_din[86]
    DIRECTION OUTPUT ;
    USE SIGNAL ;
    ANTENNADIFFAREA 0.445500 ;
    PORT
      LAYER met2 ;
        RECT 1088.450 0.000 1088.730 4.000 ;
    END
  END m_din[86]
  PIN m_din[87]
    DIRECTION OUTPUT ;
    USE SIGNAL ;
    ANTENNADIFFAREA 0.445500 ;
    PORT
      LAYER met2 ;
        RECT 1146.410 0.000 1146.690 4.000 ;
    END
  END m_din[87]
  PIN m_din[88]
    DIRECTION OUTPUT ;
    USE SIGNAL ;
    ANTENNADIFFAREA 0.445500 ;
    PORT
      LAYER met2 ;
        RECT 1098.110 0.000 1098.390 4.000 ;
    END
  END m_din[88]
  PIN m_din[89]
    DIRECTION OUTPUT ;
    USE SIGNAL ;
    ANTENNADIFFAREA 0.445500 ;
    PORT
      LAYER met2 ;
        RECT 1139.970 0.000 1140.250 4.000 ;
    END
  END m_din[89]
  PIN m_din[8]
    DIRECTION OUTPUT ;
    USE SIGNAL ;
    ANTENNADIFFAREA 0.445500 ;
    PORT
      LAYER met2 ;
        RECT 737.470 0.000 737.750 4.000 ;
    END
  END m_din[8]
  PIN m_din[90]
    DIRECTION OUTPUT ;
    USE SIGNAL ;
    ANTENNADIFFAREA 0.445500 ;
    PORT
      LAYER met2 ;
        RECT 1162.510 0.000 1162.790 4.000 ;
    END
  END m_din[90]
  PIN m_din[91]
    DIRECTION OUTPUT ;
    USE SIGNAL ;
    ANTENNADIFFAREA 0.445500 ;
    PORT
      LAYER met2 ;
        RECT 1268.770 0.000 1269.050 4.000 ;
    END
  END m_din[91]
  PIN m_din[92]
    DIRECTION OUTPUT ;
    USE SIGNAL ;
    ANTENNADIFFAREA 0.445500 ;
    PORT
      LAYER met2 ;
        RECT 1033.710 0.000 1033.990 4.000 ;
    END
  END m_din[92]
  PIN m_din[93]
    DIRECTION OUTPUT ;
    USE SIGNAL ;
    ANTENNADIFFAREA 0.445500 ;
    PORT
      LAYER met2 ;
        RECT 1007.950 0.000 1008.230 4.000 ;
    END
  END m_din[93]
  PIN m_din[94]
    DIRECTION OUTPUT ;
    USE SIGNAL ;
    ANTENNADIFFAREA 0.445500 ;
    PORT
      LAYER met2 ;
        RECT 1188.270 0.000 1188.550 4.000 ;
    END
  END m_din[94]
  PIN m_din[95]
    DIRECTION OUTPUT ;
    USE SIGNAL ;
    ANTENNADIFFAREA 0.445500 ;
    PORT
      LAYER met2 ;
        RECT 1152.850 0.000 1153.130 4.000 ;
    END
  END m_din[95]
  PIN m_din[96]
    DIRECTION OUTPUT ;
    USE SIGNAL ;
    ANTENNADIFFAREA 0.445500 ;
    PORT
      LAYER met2 ;
        RECT 946.770 0.000 947.050 4.000 ;
    END
  END m_din[96]
  PIN m_din[97]
    DIRECTION OUTPUT ;
    USE SIGNAL ;
    ANTENNADIFFAREA 0.445500 ;
    PORT
      LAYER met2 ;
        RECT 937.110 0.000 937.390 4.000 ;
    END
  END m_din[97]
  PIN m_din[98]
    DIRECTION OUTPUT ;
    USE SIGNAL ;
    ANTENNADIFFAREA 0.445500 ;
    PORT
      LAYER met2 ;
        RECT 949.990 0.000 950.270 4.000 ;
    END
  END m_din[98]
  PIN m_din[99]
    DIRECTION OUTPUT ;
    USE SIGNAL ;
    ANTENNADIFFAREA 0.445500 ;
    PORT
      LAYER met2 ;
        RECT 1223.690 0.000 1223.970 4.000 ;
    END
  END m_din[99]
  PIN m_din[9]
    DIRECTION OUTPUT ;
    USE SIGNAL ;
    ANTENNADIFFAREA 0.445500 ;
    PORT
      LAYER met2 ;
        RECT 943.550 0.000 943.830 4.000 ;
    END
  END m_din[9]
  PIN m_dout[0]
    DIRECTION INPUT ;
    USE SIGNAL ;
    ANTENNAGATEAREA 0.631200 ;
    ANTENNADIFFAREA 0.434700 ;
    PORT
      LAYER met2 ;
        RECT 1072.350 0.000 1072.630 4.000 ;
    END
  END m_dout[0]
  PIN m_dout[100]
    DIRECTION INPUT ;
    USE SIGNAL ;
    ANTENNAGATEAREA 0.631200 ;
    ANTENNADIFFAREA 0.434700 ;
    PORT
      LAYER met2 ;
        RECT 853.390 0.000 853.670 4.000 ;
    END
  END m_dout[100]
  PIN m_dout[101]
    DIRECTION INPUT ;
    USE SIGNAL ;
    ANTENNAGATEAREA 0.631200 ;
    ANTENNADIFFAREA 0.434700 ;
    PORT
      LAYER met2 ;
        RECT 959.650 0.000 959.930 4.000 ;
    END
  END m_dout[101]
  PIN m_dout[102]
    DIRECTION INPUT ;
    USE SIGNAL ;
    ANTENNAGATEAREA 0.631200 ;
    ANTENNADIFFAREA 0.434700 ;
    PORT
      LAYER met2 ;
        RECT 846.950 0.000 847.230 4.000 ;
    END
  END m_dout[102]
  PIN m_dout[103]
    DIRECTION INPUT ;
    USE SIGNAL ;
    ANTENNAGATEAREA 0.631200 ;
    ANTENNADIFFAREA 0.434700 ;
    PORT
      LAYER met2 ;
        RECT 917.790 0.000 918.070 4.000 ;
    END
  END m_dout[103]
  PIN m_dout[104]
    DIRECTION INPUT ;
    USE SIGNAL ;
    ANTENNAGATEAREA 0.631200 ;
    ANTENNADIFFAREA 0.434700 ;
    PORT
      LAYER met2 ;
        RECT 702.050 0.000 702.330 4.000 ;
    END
  END m_dout[104]
  PIN m_dout[105]
    DIRECTION INPUT ;
    USE SIGNAL ;
    ANTENNAGATEAREA 0.631200 ;
    ANTENNADIFFAREA 0.434700 ;
    PORT
      LAYER met2 ;
        RECT 930.670 0.000 930.950 4.000 ;
    END
  END m_dout[105]
  PIN m_dout[106]
    DIRECTION INPUT ;
    USE SIGNAL ;
    ANTENNAGATEAREA 0.631200 ;
    ANTENNADIFFAREA 0.434700 ;
    PORT
      LAYER met2 ;
        RECT 785.770 0.000 786.050 4.000 ;
    END
  END m_dout[106]
  PIN m_dout[107]
    DIRECTION INPUT ;
    USE SIGNAL ;
    ANTENNAGATEAREA 0.631200 ;
    ANTENNADIFFAREA 0.434700 ;
    PORT
      LAYER met2 ;
        RECT 721.370 0.000 721.650 4.000 ;
    END
  END m_dout[107]
  PIN m_dout[108]
    DIRECTION INPUT ;
    USE SIGNAL ;
    ANTENNAGATEAREA 0.631200 ;
    ANTENNADIFFAREA 0.434700 ;
    PORT
      LAYER met2 ;
        RECT 1104.550 0.000 1104.830 4.000 ;
    END
  END m_dout[108]
  PIN m_dout[109]
    DIRECTION INPUT ;
    USE SIGNAL ;
    ANTENNAGATEAREA 0.631200 ;
    ANTENNADIFFAREA 0.434700 ;
    PORT
      LAYER met2 ;
        RECT 843.730 0.000 844.010 4.000 ;
    END
  END m_dout[109]
  PIN m_dout[10]
    DIRECTION INPUT ;
    USE SIGNAL ;
    ANTENNAGATEAREA 0.631200 ;
    ANTENNADIFFAREA 0.434700 ;
    PORT
      LAYER met2 ;
        RECT 734.250 0.000 734.530 4.000 ;
    END
  END m_dout[10]
  PIN m_dout[110]
    DIRECTION INPUT ;
    USE SIGNAL ;
    ANTENNAGATEAREA 0.631200 ;
    ANTENNADIFFAREA 0.434700 ;
    PORT
      LAYER met2 ;
        RECT 872.710 0.000 872.990 4.000 ;
    END
  END m_dout[110]
  PIN m_dout[111]
    DIRECTION INPUT ;
    USE SIGNAL ;
    ANTENNAGATEAREA 0.631200 ;
    ANTENNADIFFAREA 0.434700 ;
    PORT
      LAYER met2 ;
        RECT 795.430 0.000 795.710 4.000 ;
    END
  END m_dout[111]
  PIN m_dout[112]
    DIRECTION INPUT ;
    USE SIGNAL ;
    ANTENNAGATEAREA 0.631200 ;
    ANTENNADIFFAREA 0.434700 ;
    PORT
      LAYER met2 ;
        RECT 650.530 0.000 650.810 4.000 ;
    END
  END m_dout[112]
  PIN m_dout[113]
    DIRECTION INPUT ;
    USE SIGNAL ;
    ANTENNAGATEAREA 0.631200 ;
    ANTENNADIFFAREA 0.434700 ;
    PORT
      LAYER met2 ;
        RECT 908.130 0.000 908.410 4.000 ;
    END
  END m_dout[113]
  PIN m_dout[114]
    DIRECTION INPUT ;
    USE SIGNAL ;
    ANTENNAGATEAREA 0.631200 ;
    ANTENNADIFFAREA 0.434700 ;
    PORT
      LAYER met2 ;
        RECT 969.310 0.000 969.590 4.000 ;
    END
  END m_dout[114]
  PIN m_dout[115]
    DIRECTION INPUT ;
    USE SIGNAL ;
    ANTENNAGATEAREA 0.631200 ;
    ANTENNADIFFAREA 0.434700 ;
    PORT
      LAYER met2 ;
        RECT 660.190 0.000 660.470 4.000 ;
    END
  END m_dout[115]
  PIN m_dout[116]
    DIRECTION INPUT ;
    USE SIGNAL ;
    ANTENNAGATEAREA 0.631200 ;
    ANTENNADIFFAREA 0.434700 ;
    PORT
      LAYER met2 ;
        RECT 656.970 0.000 657.250 4.000 ;
    END
  END m_dout[116]
  PIN m_dout[117]
    DIRECTION INPUT ;
    USE SIGNAL ;
    ANTENNAGATEAREA 0.631200 ;
    ANTENNADIFFAREA 0.434700 ;
    PORT
      LAYER met2 ;
        RECT 892.030 0.000 892.310 4.000 ;
    END
  END m_dout[117]
  PIN m_dout[118]
    DIRECTION INPUT ;
    USE SIGNAL ;
    ANTENNAGATEAREA 0.631200 ;
    ANTENNADIFFAREA 0.434700 ;
    PORT
      LAYER met2 ;
        RECT 1062.690 0.000 1062.970 4.000 ;
    END
  END m_dout[118]
  PIN m_dout[119]
    DIRECTION INPUT ;
    USE SIGNAL ;
    ANTENNAGATEAREA 0.631200 ;
    ANTENNADIFFAREA 0.434700 ;
    PORT
      LAYER met2 ;
        RECT 692.390 0.000 692.670 4.000 ;
    END
  END m_dout[119]
  PIN m_dout[11]
    DIRECTION INPUT ;
    USE SIGNAL ;
    ANTENNAGATEAREA 0.631200 ;
    ANTENNADIFFAREA 0.434700 ;
    PORT
      LAYER met2 ;
        RECT 898.470 0.000 898.750 4.000 ;
    END
  END m_dout[11]
  PIN m_dout[120]
    DIRECTION INPUT ;
    USE SIGNAL ;
    ANTENNAGATEAREA 0.631200 ;
    ANTENNADIFFAREA 0.434700 ;
    PORT
      LAYER met2 ;
        RECT 875.930 0.000 876.210 4.000 ;
    END
  END m_dout[120]
  PIN m_dout[121]
    DIRECTION INPUT ;
    USE SIGNAL ;
    ANTENNAGATEAREA 0.631200 ;
    ANTENNADIFFAREA 0.434700 ;
    PORT
      LAYER met2 ;
        RECT 698.830 0.000 699.110 4.000 ;
    END
  END m_dout[121]
  PIN m_dout[122]
    DIRECTION INPUT ;
    USE SIGNAL ;
    ANTENNAGATEAREA 0.631200 ;
    ANTENNADIFFAREA 0.434700 ;
    PORT
      LAYER met2 ;
        RECT 653.750 0.000 654.030 4.000 ;
    END
  END m_dout[122]
  PIN m_dout[123]
    DIRECTION INPUT ;
    USE SIGNAL ;
    ANTENNAGATEAREA 0.631200 ;
    ANTENNADIFFAREA 0.434700 ;
    PORT
      LAYER met2 ;
        RECT 895.250 0.000 895.530 4.000 ;
    END
  END m_dout[123]
  PIN m_dout[124]
    DIRECTION INPUT ;
    USE SIGNAL ;
    ANTENNAGATEAREA 0.631200 ;
    ANTENNADIFFAREA 0.434700 ;
    PORT
      LAYER met2 ;
        RECT 824.410 0.000 824.690 4.000 ;
    END
  END m_dout[124]
  PIN m_dout[125]
    DIRECTION INPUT ;
    USE SIGNAL ;
    ANTENNAGATEAREA 0.631200 ;
    ANTENNADIFFAREA 0.434700 ;
    PORT
      LAYER met2 ;
        RECT 911.350 0.000 911.630 4.000 ;
    END
  END m_dout[125]
  PIN m_dout[126]
    DIRECTION INPUT ;
    USE SIGNAL ;
    ANTENNAGATEAREA 0.631200 ;
    ANTENNADIFFAREA 0.434700 ;
    PORT
      LAYER met2 ;
        RECT 1172.170 0.000 1172.450 4.000 ;
    END
  END m_dout[126]
  PIN m_dout[127]
    DIRECTION INPUT ;
    USE SIGNAL ;
    ANTENNAGATEAREA 0.631200 ;
    ANTENNADIFFAREA 0.434700 ;
    PORT
      LAYER met2 ;
        RECT 879.150 0.000 879.430 4.000 ;
    END
  END m_dout[127]
  PIN m_dout[12]
    DIRECTION INPUT ;
    USE SIGNAL ;
    ANTENNAGATEAREA 0.631200 ;
    ANTENNADIFFAREA 0.434700 ;
    PORT
      LAYER met2 ;
        RECT 1226.910 0.000 1227.190 4.000 ;
    END
  END m_dout[12]
  PIN m_dout[13]
    DIRECTION INPUT ;
    USE SIGNAL ;
    ANTENNAGATEAREA 0.631200 ;
    ANTENNADIFFAREA 0.434700 ;
    PORT
      LAYER met2 ;
        RECT 808.310 0.000 808.590 4.000 ;
    END
  END m_dout[13]
  PIN m_dout[14]
    DIRECTION INPUT ;
    USE SIGNAL ;
    ANTENNAGATEAREA 0.631200 ;
    ANTENNADIFFAREA 0.434700 ;
    PORT
      LAYER met2 ;
        RECT 904.910 0.000 905.190 4.000 ;
    END
  END m_dout[14]
  PIN m_dout[15]
    DIRECTION INPUT ;
    USE SIGNAL ;
    ANTENNAGATEAREA 0.631200 ;
    ANTENNADIFFAREA 0.434700 ;
    PORT
      LAYER met2 ;
        RECT 1278.430 0.000 1278.710 4.000 ;
    END
  END m_dout[15]
  PIN m_dout[16]
    DIRECTION INPUT ;
    USE SIGNAL ;
    ANTENNAGATEAREA 0.631200 ;
    ANTENNADIFFAREA 0.434700 ;
    PORT
      LAYER met2 ;
        RECT 1210.810 0.000 1211.090 4.000 ;
    END
  END m_dout[16]
  PIN m_dout[17]
    DIRECTION INPUT ;
    USE SIGNAL ;
    ANTENNAGATEAREA 0.631200 ;
    ANTENNADIFFAREA 0.434700 ;
    PORT
      LAYER met2 ;
        RECT 1185.050 0.000 1185.330 4.000 ;
    END
  END m_dout[17]
  PIN m_dout[18]
    DIRECTION INPUT ;
    USE SIGNAL ;
    ANTENNAGATEAREA 0.631200 ;
    ANTENNADIFFAREA 0.434700 ;
    PORT
      LAYER met2 ;
        RECT 1040.150 0.000 1040.430 4.000 ;
    END
  END m_dout[18]
  PIN m_dout[19]
    DIRECTION INPUT ;
    USE SIGNAL ;
    ANTENNAGATEAREA 0.631200 ;
    ANTENNADIFFAREA 0.434700 ;
    PORT
      LAYER met2 ;
        RECT 995.070 0.000 995.350 4.000 ;
    END
  END m_dout[19]
  PIN m_dout[1]
    DIRECTION INPUT ;
    USE SIGNAL ;
    ANTENNAGATEAREA 0.631200 ;
    ANTENNADIFFAREA 0.434700 ;
    PORT
      LAYER met2 ;
        RECT 1204.370 0.000 1204.650 4.000 ;
    END
  END m_dout[1]
  PIN m_dout[20]
    DIRECTION INPUT ;
    USE SIGNAL ;
    ANTENNAGATEAREA 0.631200 ;
    ANTENNADIFFAREA 0.434700 ;
    PORT
      LAYER met2 ;
        RECT 1114.210 0.000 1114.490 4.000 ;
    END
  END m_dout[20]
  PIN m_dout[21]
    DIRECTION INPUT ;
    USE SIGNAL ;
    ANTENNAGATEAREA 0.631200 ;
    ANTENNADIFFAREA 0.434700 ;
    PORT
      LAYER met2 ;
        RECT 1165.730 0.000 1166.010 4.000 ;
    END
  END m_dout[21]
  PIN m_dout[22]
    DIRECTION INPUT ;
    USE SIGNAL ;
    ANTENNAGATEAREA 0.631200 ;
    ANTENNADIFFAREA 0.434700 ;
    PORT
      LAYER met2 ;
        RECT 1101.330 0.000 1101.610 4.000 ;
    END
  END m_dout[22]
  PIN m_dout[23]
    DIRECTION INPUT ;
    USE SIGNAL ;
    ANTENNAGATEAREA 0.631200 ;
    ANTENNADIFFAREA 0.434700 ;
    PORT
      LAYER met2 ;
        RECT 1075.570 0.000 1075.850 4.000 ;
    END
  END m_dout[23]
  PIN m_dout[24]
    DIRECTION INPUT ;
    USE SIGNAL ;
    ANTENNAGATEAREA 0.631200 ;
    ANTENNADIFFAREA 0.434700 ;
    PORT
      LAYER met2 ;
        RECT 1078.790 0.000 1079.070 4.000 ;
    END
  END m_dout[24]
  PIN m_dout[25]
    DIRECTION INPUT ;
    USE SIGNAL ;
    ANTENNAGATEAREA 0.631200 ;
    ANTENNADIFFAREA 0.434700 ;
    PORT
      LAYER met2 ;
        RECT 1243.010 0.000 1243.290 4.000 ;
    END
  END m_dout[25]
  PIN m_dout[26]
    DIRECTION INPUT ;
    USE SIGNAL ;
    ANTENNAGATEAREA 0.631200 ;
    ANTENNADIFFAREA 0.434700 ;
    PORT
      LAYER met2 ;
        RECT 1149.630 0.000 1149.910 4.000 ;
    END
  END m_dout[26]
  PIN m_dout[27]
    DIRECTION INPUT ;
    USE SIGNAL ;
    ANTENNAGATEAREA 0.631200 ;
    ANTENNADIFFAREA 0.434700 ;
    PORT
      LAYER met2 ;
        RECT 1255.890 0.000 1256.170 4.000 ;
    END
  END m_dout[27]
  PIN m_dout[28]
    DIRECTION INPUT ;
    USE SIGNAL ;
    ANTENNAGATEAREA 0.631200 ;
    ANTENNADIFFAREA 0.434700 ;
    PORT
      LAYER met2 ;
        RECT 1069.130 0.000 1069.410 4.000 ;
    END
  END m_dout[28]
  PIN m_dout[29]
    DIRECTION INPUT ;
    USE SIGNAL ;
    ANTENNAGATEAREA 0.631200 ;
    ANTENNADIFFAREA 0.434700 ;
    PORT
      LAYER met2 ;
        RECT 1030.490 0.000 1030.770 4.000 ;
    END
  END m_dout[29]
  PIN m_dout[2]
    DIRECTION INPUT ;
    USE SIGNAL ;
    ANTENNAGATEAREA 0.647700 ;
    ANTENNADIFFAREA 0.434700 ;
    PORT
      LAYER met2 ;
        RECT 541.050 0.000 541.330 4.000 ;
    END
  END m_dout[2]
  PIN m_dout[30]
    DIRECTION INPUT ;
    USE SIGNAL ;
    ANTENNAGATEAREA 0.631200 ;
    ANTENNADIFFAREA 0.434700 ;
    PORT
      LAYER met2 ;
        RECT 1339.610 0.000 1339.890 4.000 ;
    END
  END m_dout[30]
  PIN m_dout[31]
    DIRECTION INPUT ;
    USE SIGNAL ;
    ANTENNAGATEAREA 0.631200 ;
    ANTENNADIFFAREA 0.434700 ;
    PORT
      LAYER met2 ;
        RECT 1336.390 0.000 1336.670 4.000 ;
    END
  END m_dout[31]
  PIN m_dout[32]
    DIRECTION INPUT ;
    USE SIGNAL ;
    ANTENNAGATEAREA 0.929700 ;
    ANTENNADIFFAREA 0.434700 ;
    PORT
      LAYER met3 ;
        RECT 0.000 421.640 4.000 422.240 ;
    END
  END m_dout[32]
  PIN m_dout[33]
    DIRECTION INPUT ;
    USE SIGNAL ;
    ANTENNAGATEAREA 0.631200 ;
    ANTENNADIFFAREA 0.434700 ;
    PORT
      LAYER met2 ;
        RECT 640.870 0.000 641.150 4.000 ;
    END
  END m_dout[33]
  PIN m_dout[34]
    DIRECTION INPUT ;
    USE SIGNAL ;
    ANTENNAGATEAREA 0.631200 ;
    ANTENNADIFFAREA 0.434700 ;
    PORT
      LAYER met2 ;
        RECT 637.650 0.000 637.930 4.000 ;
    END
  END m_dout[34]
  PIN m_dout[35]
    DIRECTION INPUT ;
    USE SIGNAL ;
    ANTENNAGATEAREA 0.593700 ;
    ANTENNADIFFAREA 0.434700 ;
    PORT
      LAYER met2 ;
        RECT 634.430 0.000 634.710 4.000 ;
    END
  END m_dout[35]
  PIN m_dout[36]
    DIRECTION INPUT ;
    USE SIGNAL ;
    ANTENNAGATEAREA 0.560700 ;
    ANTENNADIFFAREA 0.434700 ;
    PORT
      LAYER met2 ;
        RECT 631.210 0.000 631.490 4.000 ;
    END
  END m_dout[36]
  PIN m_dout[37]
    DIRECTION INPUT ;
    USE SIGNAL ;
    ANTENNAGATEAREA 0.631200 ;
    ANTENNADIFFAREA 0.434700 ;
    PORT
      LAYER met2 ;
        RECT 627.990 0.000 628.270 4.000 ;
    END
  END m_dout[37]
  PIN m_dout[38]
    DIRECTION INPUT ;
    USE SIGNAL ;
    ANTENNAGATEAREA 0.647700 ;
    ANTENNADIFFAREA 0.434700 ;
    PORT
      LAYER met2 ;
        RECT 624.770 0.000 625.050 4.000 ;
    END
  END m_dout[38]
  PIN m_dout[39]
    DIRECTION INPUT ;
    USE SIGNAL ;
    ANTENNAGATEAREA 1.286700 ;
    ANTENNADIFFAREA 0.434700 ;
    PORT
      LAYER met3 ;
        RECT 0.000 618.840 4.000 619.440 ;
    END
  END m_dout[39]
  PIN m_dout[3]
    DIRECTION INPUT ;
    USE SIGNAL ;
    ANTENNAGATEAREA 0.631200 ;
    ANTENNADIFFAREA 0.434700 ;
    PORT
      LAYER met2 ;
        RECT 621.550 0.000 621.830 4.000 ;
    END
  END m_dout[3]
  PIN m_dout[40]
    DIRECTION INPUT ;
    USE SIGNAL ;
    ANTENNAGATEAREA 1.177200 ;
    ANTENNADIFFAREA 0.434700 ;
    PORT
      LAYER met3 ;
        RECT 0.000 652.840 4.000 653.440 ;
    END
  END m_dout[40]
  PIN m_dout[41]
    DIRECTION INPUT ;
    USE SIGNAL ;
    ANTENNAGATEAREA 1.286700 ;
    ANTENNADIFFAREA 0.434700 ;
    PORT
      LAYER met3 ;
        RECT 0.000 693.640 4.000 694.240 ;
    END
  END m_dout[41]
  PIN m_dout[42]
    DIRECTION INPUT ;
    USE SIGNAL ;
    ANTENNAGATEAREA 1.177200 ;
    ANTENNADIFFAREA 0.434700 ;
    PORT
      LAYER met3 ;
        RECT 0.000 578.040 4.000 578.640 ;
    END
  END m_dout[42]
  PIN m_dout[43]
    DIRECTION INPUT ;
    USE SIGNAL ;
    ANTENNAGATEAREA 1.177200 ;
    ANTENNADIFFAREA 0.434700 ;
    PORT
      LAYER met3 ;
        RECT 0.000 605.240 4.000 605.840 ;
    END
  END m_dout[43]
  PIN m_dout[44]
    DIRECTION INPUT ;
    USE SIGNAL ;
    ANTENNAGATEAREA 1.286700 ;
    ANTENNADIFFAREA 0.434700 ;
    PORT
      LAYER met3 ;
        RECT 0.000 482.840 4.000 483.440 ;
    END
  END m_dout[44]
  PIN m_dout[45]
    DIRECTION INPUT ;
    USE SIGNAL ;
    ANTENNAGATEAREA 1.177200 ;
    ANTENNADIFFAREA 0.434700 ;
    PORT
      LAYER met3 ;
        RECT 0.000 510.040 4.000 510.640 ;
    END
  END m_dout[45]
  PIN m_dout[46]
    DIRECTION INPUT ;
    USE SIGNAL ;
    ANTENNAGATEAREA 1.177200 ;
    ANTENNADIFFAREA 0.434700 ;
    PORT
      LAYER met3 ;
        RECT 0.000 459.040 4.000 459.640 ;
    END
  END m_dout[46]
  PIN m_dout[47]
    DIRECTION INPUT ;
    USE SIGNAL ;
    ANTENNAGATEAREA 1.177200 ;
    ANTENNADIFFAREA 0.434700 ;
    PORT
      LAYER met3 ;
        RECT 0.000 523.640 4.000 524.240 ;
    END
  END m_dout[47]
  PIN m_dout[48]
    DIRECTION INPUT ;
    USE SIGNAL ;
    ANTENNAGATEAREA 1.286700 ;
    ANTENNADIFFAREA 0.434700 ;
    PORT
      LAYER met3 ;
        RECT 0.000 442.040 4.000 442.640 ;
    END
  END m_dout[48]
  PIN m_dout[49]
    DIRECTION INPUT ;
    USE SIGNAL ;
    ANTENNAGATEAREA 1.286700 ;
    ANTENNADIFFAREA 0.434700 ;
    PORT
      LAYER met3 ;
        RECT 0.000 581.440 4.000 582.040 ;
    END
  END m_dout[49]
  PIN m_dout[4]
    DIRECTION INPUT ;
    USE SIGNAL ;
    ANTENNAGATEAREA 0.647700 ;
    ANTENNADIFFAREA 0.434700 ;
    PORT
      LAYER met2 ;
        RECT 618.330 0.000 618.610 4.000 ;
    END
  END m_dout[4]
  PIN m_dout[50]
    DIRECTION INPUT ;
    USE SIGNAL ;
    ANTENNAGATEAREA 1.424700 ;
    ANTENNADIFFAREA 0.434700 ;
    PORT
      LAYER met3 ;
        RECT 0.000 710.640 4.000 711.240 ;
    END
  END m_dout[50]
  PIN m_dout[51]
    DIRECTION INPUT ;
    USE SIGNAL ;
    ANTENNAGATEAREA 1.286700 ;
    ANTENNADIFFAREA 0.434700 ;
    PORT
      LAYER met3 ;
        RECT 0.000 642.640 4.000 643.240 ;
    END
  END m_dout[51]
  PIN m_dout[52]
    DIRECTION INPUT ;
    USE SIGNAL ;
    ANTENNAGATEAREA 1.286700 ;
    ANTENNADIFFAREA 0.434700 ;
    PORT
      LAYER met3 ;
        RECT 0.000 561.040 4.000 561.640 ;
    END
  END m_dout[52]
  PIN m_dout[53]
    DIRECTION INPUT ;
    USE SIGNAL ;
    ANTENNAGATEAREA 1.286700 ;
    ANTENNADIFFAREA 0.434700 ;
    PORT
      LAYER met3 ;
        RECT 0.000 574.640 4.000 575.240 ;
    END
  END m_dout[53]
  PIN m_dout[54]
    DIRECTION INPUT ;
    USE SIGNAL ;
    ANTENNAGATEAREA 1.286700 ;
    ANTENNADIFFAREA 0.434700 ;
    PORT
      LAYER met3 ;
        RECT 0.000 591.640 4.000 592.240 ;
    END
  END m_dout[54]
  PIN m_dout[55]
    DIRECTION INPUT ;
    USE SIGNAL ;
    ANTENNAGATEAREA 1.424700 ;
    ANTENNADIFFAREA 0.434700 ;
    PORT
      LAYER met3 ;
        RECT 0.000 496.440 4.000 497.040 ;
    END
  END m_dout[55]
  PIN m_dout[56]
    DIRECTION INPUT ;
    USE SIGNAL ;
    ANTENNAGATEAREA 1.424700 ;
    ANTENNADIFFAREA 0.434700 ;
    PORT
      LAYER met3 ;
        RECT 0.000 703.840 4.000 704.440 ;
    END
  END m_dout[56]
  PIN m_dout[57]
    DIRECTION INPUT ;
    USE SIGNAL ;
    ANTENNAGATEAREA 1.424700 ;
    ANTENNADIFFAREA 0.434700 ;
    PORT
      LAYER met3 ;
        RECT 0.000 622.240 4.000 622.840 ;
    END
  END m_dout[57]
  PIN m_dout[58]
    DIRECTION INPUT ;
    USE SIGNAL ;
    ANTENNAGATEAREA 1.424700 ;
    ANTENNADIFFAREA 0.434700 ;
    PORT
      LAYER met3 ;
        RECT 0.000 608.640 4.000 609.240 ;
    END
  END m_dout[58]
  PIN m_dout[59]
    DIRECTION INPUT ;
    USE SIGNAL ;
    ANTENNAGATEAREA 1.286700 ;
    ANTENNADIFFAREA 0.434700 ;
    PORT
      LAYER met3 ;
        RECT 0.000 472.640 4.000 473.240 ;
    END
  END m_dout[59]
  PIN m_dout[5]
    DIRECTION INPUT ;
    USE SIGNAL ;
    ANTENNAGATEAREA 0.631200 ;
    ANTENNADIFFAREA 0.434700 ;
    PORT
      LAYER met2 ;
        RECT 615.110 0.000 615.390 4.000 ;
    END
  END m_dout[5]
  PIN m_dout[60]
    DIRECTION INPUT ;
    USE SIGNAL ;
    ANTENNAGATEAREA 1.424700 ;
    ANTENNADIFFAREA 0.434700 ;
    PORT
      LAYER met3 ;
        RECT 0.000 683.440 4.000 684.040 ;
    END
  END m_dout[60]
  PIN m_dout[61]
    DIRECTION INPUT ;
    USE SIGNAL ;
    ANTENNAGATEAREA 1.286700 ;
    ANTENNADIFFAREA 0.434700 ;
    PORT
      LAYER met3 ;
        RECT 0.000 520.240 4.000 520.840 ;
    END
  END m_dout[61]
  PIN m_dout[62]
    DIRECTION INPUT ;
    USE SIGNAL ;
    ANTENNAGATEAREA 1.286700 ;
    ANTENNADIFFAREA 0.434700 ;
    PORT
      LAYER met3 ;
        RECT 0.000 666.440 4.000 667.040 ;
    END
  END m_dout[62]
  PIN m_dout[63]
    DIRECTION INPUT ;
    USE SIGNAL ;
    ANTENNAGATEAREA 1.286700 ;
    ANTENNADIFFAREA 0.434700 ;
    PORT
      LAYER met3 ;
        RECT 0.000 598.440 4.000 599.040 ;
    END
  END m_dout[63]
  PIN m_dout[64]
    DIRECTION INPUT ;
    USE SIGNAL ;
    ANTENNAGATEAREA 1.286700 ;
    ANTENNADIFFAREA 0.434700 ;
    PORT
      LAYER met3 ;
        RECT 0.000 462.440 4.000 463.040 ;
    END
  END m_dout[64]
  PIN m_dout[65]
    DIRECTION INPUT ;
    USE SIGNAL ;
    ANTENNAGATEAREA 0.593700 ;
    ANTENNADIFFAREA 0.434700 ;
    PORT
      LAYER met2 ;
        RECT 611.890 0.000 612.170 4.000 ;
    END
  END m_dout[65]
  PIN m_dout[66]
    DIRECTION INPUT ;
    USE SIGNAL ;
    ANTENNAGATEAREA 0.647700 ;
    ANTENNADIFFAREA 0.434700 ;
    PORT
      LAYER met2 ;
        RECT 608.670 0.000 608.950 4.000 ;
    END
  END m_dout[66]
  PIN m_dout[67]
    DIRECTION INPUT ;
    USE SIGNAL ;
    ANTENNAGATEAREA 0.593700 ;
    ANTENNADIFFAREA 0.434700 ;
    PORT
      LAYER met2 ;
        RECT 605.450 0.000 605.730 4.000 ;
    END
  END m_dout[67]
  PIN m_dout[68]
    DIRECTION INPUT ;
    USE SIGNAL ;
    ANTENNAGATEAREA 0.647700 ;
    ANTENNADIFFAREA 0.434700 ;
    PORT
      LAYER met2 ;
        RECT 602.230 0.000 602.510 4.000 ;
    END
  END m_dout[68]
  PIN m_dout[69]
    DIRECTION INPUT ;
    USE SIGNAL ;
    ANTENNAGATEAREA 0.647700 ;
    ANTENNADIFFAREA 0.434700 ;
    PORT
      LAYER met2 ;
        RECT 599.010 0.000 599.290 4.000 ;
    END
  END m_dout[69]
  PIN m_dout[6]
    DIRECTION INPUT ;
    USE SIGNAL ;
    ANTENNAGATEAREA 0.647700 ;
    ANTENNADIFFAREA 0.434700 ;
    PORT
      LAYER met2 ;
        RECT 595.790 0.000 596.070 4.000 ;
    END
  END m_dout[6]
  PIN m_dout[70]
    DIRECTION INPUT ;
    USE SIGNAL ;
    ANTENNAGATEAREA 0.647700 ;
    ANTENNADIFFAREA 0.434700 ;
    PORT
      LAYER met2 ;
        RECT 592.570 0.000 592.850 4.000 ;
    END
  END m_dout[70]
  PIN m_dout[71]
    DIRECTION INPUT ;
    USE SIGNAL ;
    ANTENNAGATEAREA 1.286700 ;
    ANTENNADIFFAREA 0.434700 ;
    PORT
      LAYER met3 ;
        RECT 0.000 612.040 4.000 612.640 ;
    END
  END m_dout[71]
  PIN m_dout[72]
    DIRECTION INPUT ;
    USE SIGNAL ;
    ANTENNAGATEAREA 0.929700 ;
    ANTENNADIFFAREA 0.434700 ;
    PORT
      LAYER met3 ;
        RECT 0.000 680.040 4.000 680.640 ;
    END
  END m_dout[72]
  PIN m_dout[73]
    DIRECTION INPUT ;
    USE SIGNAL ;
    ANTENNAGATEAREA 1.177200 ;
    ANTENNADIFFAREA 0.434700 ;
    PORT
      LAYER met3 ;
        RECT 0.000 425.040 4.000 425.640 ;
    END
  END m_dout[73]
  PIN m_dout[74]
    DIRECTION INPUT ;
    USE SIGNAL ;
    ANTENNAGATEAREA 1.286700 ;
    ANTENNADIFFAREA 0.434700 ;
    PORT
      LAYER met3 ;
        RECT 0.000 720.840 4.000 721.440 ;
    END
  END m_dout[74]
  PIN m_dout[75]
    DIRECTION INPUT ;
    USE SIGNAL ;
    ANTENNAGATEAREA 1.177200 ;
    ANTENNADIFFAREA 0.434700 ;
    PORT
      LAYER met3 ;
        RECT 0.000 673.240 4.000 673.840 ;
    END
  END m_dout[75]
  PIN m_dout[76]
    DIRECTION INPUT ;
    USE SIGNAL ;
    ANTENNAGATEAREA 1.286700 ;
    ANTENNADIFFAREA 0.434700 ;
    PORT
      LAYER met3 ;
        RECT 0.000 438.640 4.000 439.240 ;
    END
  END m_dout[76]
  PIN m_dout[77]
    DIRECTION INPUT ;
    USE SIGNAL ;
    ANTENNAGATEAREA 1.177200 ;
    ANTENNADIFFAREA 0.434700 ;
    PORT
      LAYER met3 ;
        RECT 0.000 445.440 4.000 446.040 ;
    END
  END m_dout[77]
  PIN m_dout[78]
    DIRECTION INPUT ;
    USE SIGNAL ;
    ANTENNAGATEAREA 1.177200 ;
    ANTENNADIFFAREA 0.434700 ;
    PORT
      LAYER met3 ;
        RECT 0.000 499.840 4.000 500.440 ;
    END
  END m_dout[78]
  PIN m_dout[79]
    DIRECTION INPUT ;
    USE SIGNAL ;
    ANTENNAGATEAREA 1.177200 ;
    ANTENNADIFFAREA 0.434700 ;
    PORT
      LAYER met3 ;
        RECT 0.000 448.840 4.000 449.440 ;
    END
  END m_dout[79]
  PIN m_dout[7]
    DIRECTION INPUT ;
    USE SIGNAL ;
    ANTENNAGATEAREA 1.286700 ;
    ANTENNADIFFAREA 0.434700 ;
    PORT
      LAYER met3 ;
        RECT 0.000 625.640 4.000 626.240 ;
    END
  END m_dout[7]
  PIN m_dout[80]
    DIRECTION INPUT ;
    USE SIGNAL ;
    ANTENNAGATEAREA 1.424700 ;
    ANTENNADIFFAREA 0.434700 ;
    PORT
      LAYER met3 ;
        RECT 0.000 503.240 4.000 503.840 ;
    END
  END m_dout[80]
  PIN m_dout[81]
    DIRECTION INPUT ;
    USE SIGNAL ;
    ANTENNAGATEAREA 1.286700 ;
    ANTENNADIFFAREA 0.434700 ;
    PORT
      LAYER met3 ;
        RECT 0.000 554.240 4.000 554.840 ;
    END
  END m_dout[81]
  PIN m_dout[82]
    DIRECTION INPUT ;
    USE SIGNAL ;
    ANTENNAGATEAREA 1.286700 ;
    ANTENNADIFFAREA 0.434700 ;
    PORT
      LAYER met3 ;
        RECT 0.000 476.040 4.000 476.640 ;
    END
  END m_dout[82]
  PIN m_dout[83]
    DIRECTION INPUT ;
    USE SIGNAL ;
    ANTENNAGATEAREA 0.631200 ;
    ANTENNADIFFAREA 0.434700 ;
    PORT
      LAYER met2 ;
        RECT 1291.310 0.000 1291.590 4.000 ;
    END
  END m_dout[83]
  PIN m_dout[84]
    DIRECTION INPUT ;
    USE SIGNAL ;
    ANTENNAGATEAREA 1.286700 ;
    ANTENNADIFFAREA 0.434700 ;
    PORT
      LAYER met3 ;
        RECT 0.000 479.440 4.000 480.040 ;
    END
  END m_dout[84]
  PIN m_dout[85]
    DIRECTION INPUT ;
    USE SIGNAL ;
    ANTENNAGATEAREA 0.682200 ;
    ANTENNADIFFAREA 0.434700 ;
    PORT
      LAYER met2 ;
        RECT 589.350 0.000 589.630 4.000 ;
    END
  END m_dout[85]
  PIN m_dout[86]
    DIRECTION INPUT ;
    USE SIGNAL ;
    ANTENNAGATEAREA 0.647700 ;
    ANTENNADIFFAREA 0.434700 ;
    PORT
      LAYER met2 ;
        RECT 1307.410 0.000 1307.690 4.000 ;
    END
  END m_dout[86]
  PIN m_dout[87]
    DIRECTION INPUT ;
    USE SIGNAL ;
    ANTENNAGATEAREA 0.560700 ;
    ANTENNADIFFAREA 0.434700 ;
    PORT
      LAYER met2 ;
        RECT 1317.070 0.000 1317.350 4.000 ;
    END
  END m_dout[87]
  PIN m_dout[88]
    DIRECTION INPUT ;
    USE SIGNAL ;
    ANTENNAGATEAREA 0.631200 ;
    ANTENNADIFFAREA 0.434700 ;
    PORT
      LAYER met2 ;
        RECT 1310.630 0.000 1310.910 4.000 ;
    END
  END m_dout[88]
  PIN m_dout[89]
    DIRECTION INPUT ;
    USE SIGNAL ;
    ANTENNAGATEAREA 0.560700 ;
    ANTENNADIFFAREA 0.434700 ;
    PORT
      LAYER met2 ;
        RECT 1333.170 0.000 1333.450 4.000 ;
    END
  END m_dout[89]
  PIN m_dout[8]
    DIRECTION INPUT ;
    USE SIGNAL ;
    ANTENNAGATEAREA 0.929700 ;
    ANTENNADIFFAREA 0.434700 ;
    PORT
      LAYER met3 ;
        RECT 0.000 690.240 4.000 690.840 ;
    END
  END m_dout[8]
  PIN m_dout[90]
    DIRECTION INPUT ;
    USE SIGNAL ;
    ANTENNAGATEAREA 1.424700 ;
    ANTENNADIFFAREA 0.434700 ;
    PORT
      LAYER met3 ;
        RECT 0.000 544.040 4.000 544.640 ;
    END
  END m_dout[90]
  PIN m_dout[91]
    DIRECTION INPUT ;
    USE SIGNAL ;
    ANTENNAGATEAREA 0.631200 ;
    ANTENNADIFFAREA 0.434700 ;
    PORT
      LAYER met2 ;
        RECT 1320.290 0.000 1320.570 4.000 ;
    END
  END m_dout[91]
  PIN m_dout[92]
    DIRECTION INPUT ;
    USE SIGNAL ;
    ANTENNAGATEAREA 0.631200 ;
    ANTENNADIFFAREA 0.434700 ;
    PORT
      LAYER met2 ;
        RECT 1300.970 0.000 1301.250 4.000 ;
    END
  END m_dout[92]
  PIN m_dout[93]
    DIRECTION INPUT ;
    USE SIGNAL ;
    ANTENNAGATEAREA 0.647700 ;
    ANTENNADIFFAREA 0.434700 ;
    PORT
      LAYER met2 ;
        RECT 586.130 0.000 586.410 4.000 ;
    END
  END m_dout[93]
  PIN m_dout[94]
    DIRECTION INPUT ;
    USE SIGNAL ;
    ANTENNAGATEAREA 0.631200 ;
    ANTENNADIFFAREA 0.434700 ;
    PORT
      LAYER met2 ;
        RECT 1304.190 0.000 1304.470 4.000 ;
    END
  END m_dout[94]
  PIN m_dout[95]
    DIRECTION INPUT ;
    USE SIGNAL ;
    ANTENNAGATEAREA 0.560700 ;
    ANTENNADIFFAREA 0.434700 ;
    PORT
      LAYER met2 ;
        RECT 1323.510 0.000 1323.790 4.000 ;
    END
  END m_dout[95]
  PIN m_dout[96]
    DIRECTION INPUT ;
    USE SIGNAL ;
    ANTENNAGATEAREA 1.177200 ;
    ANTENNADIFFAREA 0.434700 ;
    PORT
      LAYER met3 ;
        RECT 0.000 540.640 4.000 541.240 ;
    END
  END m_dout[96]
  PIN m_dout[97]
    DIRECTION INPUT ;
    USE SIGNAL ;
    ANTENNAGATEAREA 0.593700 ;
    ANTENNADIFFAREA 0.434700 ;
    PORT
      LAYER met2 ;
        RECT 582.910 0.000 583.190 4.000 ;
    END
  END m_dout[97]
  PIN m_dout[98]
    DIRECTION INPUT ;
    USE SIGNAL ;
    ANTENNAGATEAREA 0.593700 ;
    ANTENNADIFFAREA 0.434700 ;
    PORT
      LAYER met2 ;
        RECT 579.690 0.000 579.970 4.000 ;
    END
  END m_dout[98]
  PIN m_dout[99]
    DIRECTION INPUT ;
    USE SIGNAL ;
    ANTENNAGATEAREA 0.631200 ;
    ANTENNADIFFAREA 0.434700 ;
    PORT
      LAYER met2 ;
        RECT 576.470 0.000 576.750 4.000 ;
    END
  END m_dout[99]
  PIN m_dout[9]
    DIRECTION INPUT ;
    USE SIGNAL ;
    ANTENNAGATEAREA 1.177200 ;
    ANTENNADIFFAREA 0.434700 ;
    PORT
      LAYER met3 ;
        RECT 0.000 571.240 4.000 571.840 ;
    END
  END m_dout[9]
  PIN m_stall
    DIRECTION INPUT ;
    USE SIGNAL ;
    ANTENNAGATEAREA 0.929700 ;
    ANTENNADIFFAREA 0.434700 ;
    PORT
      LAYER met3 ;
        RECT 0.000 639.240 4.000 639.840 ;
    END
  END m_stall
  PIN m_web
    DIRECTION OUTPUT ;
    USE SIGNAL ;
    ANTENNADIFFAREA 0.445500 ;
    PORT
      LAYER met3 ;
        RECT 0.000 717.440 4.000 718.040 ;
    END
  END m_web
  PIN rdata[0]
    DIRECTION OUTPUT ;
    USE SIGNAL ;
    ANTENNADIFFAREA 0.445500 ;
    PORT
      LAYER met3 ;
        RECT 0.000 530.440 4.000 531.040 ;
    END
  END rdata[0]
  PIN rdata[10]
    DIRECTION OUTPUT ;
    USE SIGNAL ;
    ANTENNADIFFAREA 0.445500 ;
    PORT
      LAYER met3 ;
        RECT 0.000 700.440 4.000 701.040 ;
    END
  END rdata[10]
  PIN rdata[11]
    DIRECTION OUTPUT ;
    USE SIGNAL ;
    ANTENNADIFFAREA 0.445500 ;
    PORT
      LAYER met3 ;
        RECT 0.000 697.040 4.000 697.640 ;
    END
  END rdata[11]
  PIN rdata[12]
    DIRECTION OUTPUT ;
    USE SIGNAL ;
    ANTENNADIFFAREA 0.445500 ;
    PORT
      LAYER met3 ;
        RECT 0.000 489.640 4.000 490.240 ;
    END
  END rdata[12]
  PIN rdata[13]
    DIRECTION OUTPUT ;
    USE SIGNAL ;
    ANTENNADIFFAREA 0.445500 ;
    PORT
      LAYER met3 ;
        RECT 0.000 527.040 4.000 527.640 ;
    END
  END rdata[13]
  PIN rdata[14]
    DIRECTION OUTPUT ;
    USE SIGNAL ;
    ANTENNADIFFAREA 0.445500 ;
    PORT
      LAYER met3 ;
        RECT 0.000 465.840 4.000 466.440 ;
    END
  END rdata[14]
  PIN rdata[15]
    DIRECTION OUTPUT ;
    USE SIGNAL ;
    ANTENNADIFFAREA 0.445500 ;
    PORT
      LAYER met3 ;
        RECT 0.000 435.240 4.000 435.840 ;
    END
  END rdata[15]
  PIN rdata[16]
    DIRECTION OUTPUT ;
    USE SIGNAL ;
    ANTENNADIFFAREA 0.445500 ;
    PORT
      LAYER met3 ;
        RECT 0.000 567.840 4.000 568.440 ;
    END
  END rdata[16]
  PIN rdata[17]
    DIRECTION OUTPUT ;
    USE SIGNAL ;
    ANTENNADIFFAREA 0.445500 ;
    PORT
      LAYER met3 ;
        RECT 0.000 428.440 4.000 429.040 ;
    END
  END rdata[17]
  PIN rdata[18]
    DIRECTION OUTPUT ;
    USE SIGNAL ;
    ANTENNADIFFAREA 0.445500 ;
    PORT
      LAYER met3 ;
        RECT 0.000 727.640 4.000 728.240 ;
    END
  END rdata[18]
  PIN rdata[19]
    DIRECTION OUTPUT ;
    USE SIGNAL ;
    ANTENNADIFFAREA 0.445500 ;
    PORT
      LAYER met3 ;
        RECT 0.000 550.840 4.000 551.440 ;
    END
  END rdata[19]
  PIN rdata[1]
    DIRECTION OUTPUT ;
    USE SIGNAL ;
    ANTENNADIFFAREA 0.445500 ;
    PORT
      LAYER met2 ;
        RECT 573.250 0.000 573.530 4.000 ;
    END
  END rdata[1]
  PIN rdata[20]
    DIRECTION OUTPUT ;
    USE SIGNAL ;
    ANTENNADIFFAREA 0.445500 ;
    PORT
      LAYER met3 ;
        RECT 0.000 431.840 4.000 432.440 ;
    END
  END rdata[20]
  PIN rdata[21]
    DIRECTION OUTPUT ;
    USE SIGNAL ;
    ANTENNADIFFAREA 0.445500 ;
    PORT
      LAYER met2 ;
        RECT 570.030 0.000 570.310 4.000 ;
    END
  END rdata[21]
  PIN rdata[22]
    DIRECTION OUTPUT ;
    USE SIGNAL ;
    ANTENNADIFFAREA 0.445500 ;
    PORT
      LAYER met2 ;
        RECT 566.810 0.000 567.090 4.000 ;
    END
  END rdata[22]
  PIN rdata[23]
    DIRECTION OUTPUT ;
    USE SIGNAL ;
    ANTENNADIFFAREA 0.445500 ;
    PORT
      LAYER met2 ;
        RECT 563.590 0.000 563.870 4.000 ;
    END
  END rdata[23]
  PIN rdata[24]
    DIRECTION OUTPUT ;
    USE SIGNAL ;
    ANTENNADIFFAREA 0.445500 ;
    PORT
      LAYER met2 ;
        RECT 1313.850 0.000 1314.130 4.000 ;
    END
  END rdata[24]
  PIN rdata[25]
    DIRECTION OUTPUT ;
    USE SIGNAL ;
    ANTENNADIFFAREA 0.445500 ;
    PORT
      LAYER met2 ;
        RECT 1297.750 0.000 1298.030 4.000 ;
    END
  END rdata[25]
  PIN rdata[26]
    DIRECTION OUTPUT ;
    USE SIGNAL ;
    ANTENNADIFFAREA 0.445500 ;
    PORT
      LAYER met3 ;
        RECT 0.000 506.640 4.000 507.240 ;
    END
  END rdata[26]
  PIN rdata[27]
    DIRECTION OUTPUT ;
    USE SIGNAL ;
    ANTENNADIFFAREA 0.445500 ;
    PORT
      LAYER met2 ;
        RECT 1326.730 0.000 1327.010 4.000 ;
    END
  END rdata[27]
  PIN rdata[28]
    DIRECTION OUTPUT ;
    USE SIGNAL ;
    ANTENNADIFFAREA 0.445500 ;
    PORT
      LAYER met2 ;
        RECT 1294.530 0.000 1294.810 4.000 ;
    END
  END rdata[28]
  PIN rdata[29]
    DIRECTION OUTPUT ;
    USE SIGNAL ;
    ANTENNADIFFAREA 0.445500 ;
    PORT
      LAYER met2 ;
        RECT 560.370 0.000 560.650 4.000 ;
    END
  END rdata[29]
  PIN rdata[2]
    DIRECTION OUTPUT ;
    USE SIGNAL ;
    ANTENNADIFFAREA 0.445500 ;
    PORT
      LAYER met3 ;
        RECT 0.000 469.240 4.000 469.840 ;
    END
  END rdata[2]
  PIN rdata[30]
    DIRECTION OUTPUT ;
    USE SIGNAL ;
    ANTENNADIFFAREA 0.445500 ;
    PORT
      LAYER met2 ;
        RECT 1329.950 0.000 1330.230 4.000 ;
    END
  END rdata[30]
  PIN rdata[31]
    DIRECTION OUTPUT ;
    USE SIGNAL ;
    ANTENNADIFFAREA 0.445500 ;
    PORT
      LAYER met2 ;
        RECT 1288.090 0.000 1288.370 4.000 ;
    END
  END rdata[31]
  PIN rdata[3]
    DIRECTION OUTPUT ;
    USE SIGNAL ;
    ANTENNADIFFAREA 0.445500 ;
    PORT
      LAYER met2 ;
        RECT 557.150 0.000 557.430 4.000 ;
    END
  END rdata[3]
  PIN rdata[4]
    DIRECTION OUTPUT ;
    USE SIGNAL ;
    ANTENNADIFFAREA 0.445500 ;
    PORT
      LAYER met2 ;
        RECT 553.930 0.000 554.210 4.000 ;
    END
  END rdata[4]
  PIN rdata[5]
    DIRECTION OUTPUT ;
    USE SIGNAL ;
    ANTENNADIFFAREA 0.445500 ;
    PORT
      LAYER met3 ;
        RECT 0.000 537.240 4.000 537.840 ;
    END
  END rdata[5]
  PIN rdata[6]
    DIRECTION OUTPUT ;
    USE SIGNAL ;
    ANTENNADIFFAREA 0.445500 ;
    PORT
      LAYER met2 ;
        RECT 550.710 0.000 550.990 4.000 ;
    END
  END rdata[6]
  PIN rdata[7]
    DIRECTION OUTPUT ;
    USE SIGNAL ;
    ANTENNADIFFAREA 0.445500 ;
    PORT
      LAYER met3 ;
        RECT 0.000 547.440 4.000 548.040 ;
    END
  END rdata[7]
  PIN rdata[8]
    DIRECTION OUTPUT ;
    USE SIGNAL ;
    ANTENNADIFFAREA 0.445500 ;
    PORT
      LAYER met3 ;
        RECT 0.000 595.040 4.000 595.640 ;
    END
  END rdata[8]
  PIN rdata[9]
    DIRECTION OUTPUT ;
    USE SIGNAL ;
    ANTENNADIFFAREA 0.445500 ;
    PORT
      LAYER met3 ;
        RECT 0.000 724.240 4.000 724.840 ;
    END
  END rdata[9]
  PIN rst_n
    DIRECTION INPUT ;
    USE SIGNAL ;
    ANTENNAGATEAREA 1.424700 ;
    ANTENNADIFFAREA 0.434700 ;
    PORT
      LAYER met3 ;
        RECT 2436.915 680.040 2440.915 680.640 ;
    END
  END rst_n
  PIN sel
    DIRECTION INPUT ;
    USE SIGNAL ;
    ANTENNAGATEAREA 0.860700 ;
    ANTENNADIFFAREA 0.434700 ;
    PORT
      LAYER met3 ;
        RECT 0.000 632.440 4.000 633.040 ;
    END
  END sel
  PIN wdata[0]
    DIRECTION INPUT ;
    USE SIGNAL ;
    ANTENNAGATEAREA 0.929700 ;
    ANTENNADIFFAREA 0.434700 ;
    PORT
      LAYER met3 ;
        RECT 0.000 629.040 4.000 629.640 ;
    END
  END wdata[0]
  PIN wdata[10]
    DIRECTION INPUT ;
    USE SIGNAL ;
    ANTENNAGATEAREA 1.177200 ;
    ANTENNADIFFAREA 0.434700 ;
    PORT
      LAYER met3 ;
        RECT 0.000 584.840 4.000 585.440 ;
    END
  END wdata[10]
  PIN wdata[11]
    DIRECTION INPUT ;
    USE SIGNAL ;
    ANTENNAGATEAREA 1.177200 ;
    ANTENNADIFFAREA 0.434700 ;
    PORT
      LAYER met3 ;
        RECT 0.000 676.640 4.000 677.240 ;
    END
  END wdata[11]
  PIN wdata[12]
    DIRECTION INPUT ;
    USE SIGNAL ;
    ANTENNAGATEAREA 0.860700 ;
    ANTENNADIFFAREA 0.434700 ;
    PORT
      LAYER met3 ;
        RECT 0.000 486.240 4.000 486.840 ;
    END
  END wdata[12]
  PIN wdata[13]
    DIRECTION INPUT ;
    USE SIGNAL ;
    ANTENNAGATEAREA 0.860700 ;
    ANTENNADIFFAREA 0.434700 ;
    PORT
      LAYER met3 ;
        RECT 0.000 452.240 4.000 452.840 ;
    END
  END wdata[13]
  PIN wdata[14]
    DIRECTION INPUT ;
    USE SIGNAL ;
    ANTENNAGATEAREA 0.860700 ;
    ANTENNADIFFAREA 0.434700 ;
    PORT
      LAYER met3 ;
        RECT 0.000 455.640 4.000 456.240 ;
    END
  END wdata[14]
  PIN wdata[15]
    DIRECTION INPUT ;
    USE SIGNAL ;
    ANTENNAGATEAREA 0.929700 ;
    ANTENNADIFFAREA 0.434700 ;
    PORT
      LAYER met3 ;
        RECT 0.000 513.440 4.000 514.040 ;
    END
  END wdata[15]
  PIN wdata[16]
    DIRECTION INPUT ;
    USE SIGNAL ;
    ANTENNAGATEAREA 0.929700 ;
    ANTENNADIFFAREA 0.434700 ;
    PORT
      LAYER met3 ;
        RECT 0.000 686.840 4.000 687.440 ;
    END
  END wdata[16]
  PIN wdata[17]
    DIRECTION INPUT ;
    USE SIGNAL ;
    ANTENNAGATEAREA 0.860700 ;
    ANTENNADIFFAREA 0.434700 ;
    PORT
      LAYER met3 ;
        RECT 0.000 557.640 4.000 558.240 ;
    END
  END wdata[17]
  PIN wdata[18]
    DIRECTION INPUT ;
    USE SIGNAL ;
    ANTENNAGATEAREA 0.682200 ;
    ANTENNADIFFAREA 0.434700 ;
    PORT
      LAYER met3 ;
        RECT 0.000 707.240 4.000 707.840 ;
    END
  END wdata[18]
  PIN wdata[19]
    DIRECTION INPUT ;
    USE SIGNAL ;
    ANTENNAGATEAREA 0.647700 ;
    ANTENNADIFFAREA 0.434700 ;
    PORT
      LAYER met3 ;
        RECT 0.000 533.840 4.000 534.440 ;
    END
  END wdata[19]
  PIN wdata[1]
    DIRECTION INPUT ;
    USE SIGNAL ;
    ANTENNAGATEAREA 1.177200 ;
    ANTENNADIFFAREA 0.434700 ;
    PORT
      LAYER met3 ;
        RECT 0.000 646.040 4.000 646.640 ;
    END
  END wdata[1]
  PIN wdata[20]
    DIRECTION INPUT ;
    USE SIGNAL ;
    ANTENNAGATEAREA 0.682200 ;
    ANTENNADIFFAREA 0.434700 ;
    PORT
      LAYER met3 ;
        RECT 0.000 564.440 4.000 565.040 ;
    END
  END wdata[20]
  PIN wdata[21]
    DIRECTION INPUT ;
    USE SIGNAL ;
    PORT
      LAYER met2 ;
        RECT 6.530 0.000 6.810 4.000 ;
    END
  END wdata[21]
  PIN wdata[22]
    DIRECTION INPUT ;
    USE SIGNAL ;
    PORT
      LAYER met2 ;
        RECT 9.750 0.000 10.030 4.000 ;
    END
  END wdata[22]
  PIN wdata[23]
    DIRECTION INPUT ;
    USE SIGNAL ;
    PORT
      LAYER met2 ;
        RECT 12.970 0.000 13.250 4.000 ;
    END
  END wdata[23]
  PIN wdata[24]
    DIRECTION INPUT ;
    USE SIGNAL ;
    PORT
      LAYER met2 ;
        RECT 16.190 0.000 16.470 4.000 ;
    END
  END wdata[24]
  PIN wdata[25]
    DIRECTION INPUT ;
    USE SIGNAL ;
    PORT
      LAYER met2 ;
        RECT 19.410 0.000 19.690 4.000 ;
    END
  END wdata[25]
  PIN wdata[26]
    DIRECTION INPUT ;
    USE SIGNAL ;
    PORT
      LAYER met2 ;
        RECT 22.630 0.000 22.910 4.000 ;
    END
  END wdata[26]
  PIN wdata[27]
    DIRECTION INPUT ;
    USE SIGNAL ;
    PORT
      LAYER met2 ;
        RECT 29.070 0.000 29.350 4.000 ;
    END
  END wdata[27]
  PIN wdata[28]
    DIRECTION INPUT ;
    USE SIGNAL ;
    PORT
      LAYER met2 ;
        RECT 32.290 0.000 32.570 4.000 ;
    END
  END wdata[28]
  PIN wdata[29]
    DIRECTION INPUT ;
    USE SIGNAL ;
    PORT
      LAYER met2 ;
        RECT 35.510 0.000 35.790 4.000 ;
    END
  END wdata[29]
  PIN wdata[2]
    DIRECTION INPUT ;
    USE SIGNAL ;
    ANTENNAGATEAREA 0.860700 ;
    ANTENNADIFFAREA 0.434700 ;
    PORT
      LAYER met3 ;
        RECT 0.000 714.040 4.000 714.640 ;
    END
  END wdata[2]
  PIN wdata[30]
    DIRECTION INPUT ;
    USE SIGNAL ;
    PORT
      LAYER met2 ;
        RECT 38.730 0.000 39.010 4.000 ;
    END
  END wdata[30]
  PIN wdata[31]
    DIRECTION INPUT ;
    USE SIGNAL ;
    PORT
      LAYER met2 ;
        RECT 41.950 0.000 42.230 4.000 ;
    END
  END wdata[31]
  PIN wdata[3]
    DIRECTION INPUT ;
    USE SIGNAL ;
    ANTENNAGATEAREA 0.682200 ;
    ANTENNADIFFAREA 0.434700 ;
    PORT
      LAYER met3 ;
        RECT 0.000 493.040 4.000 493.640 ;
    END
  END wdata[3]
  PIN wdata[4]
    DIRECTION INPUT ;
    USE SIGNAL ;
    ANTENNAGATEAREA 0.929700 ;
    ANTENNADIFFAREA 0.434700 ;
    PORT
      LAYER met3 ;
        RECT 0.000 516.840 4.000 517.440 ;
    END
  END wdata[4]
  PIN wdata[5]
    DIRECTION INPUT ;
    USE SIGNAL ;
    ANTENNAGATEAREA 0.682200 ;
    ANTENNADIFFAREA 0.434700 ;
    PORT
      LAYER met2 ;
        RECT 547.490 0.000 547.770 4.000 ;
    END
  END wdata[5]
  PIN wdata[6]
    DIRECTION INPUT ;
    USE SIGNAL ;
    ANTENNAGATEAREA 0.682200 ;
    ANTENNADIFFAREA 0.434700 ;
    PORT
      LAYER met2 ;
        RECT 544.270 0.000 544.550 4.000 ;
    END
  END wdata[6]
  PIN wdata[7]
    DIRECTION INPUT ;
    USE SIGNAL ;
    ANTENNAGATEAREA 0.929700 ;
    ANTENNADIFFAREA 0.434700 ;
    PORT
      LAYER met3 ;
        RECT 0.000 615.440 4.000 616.040 ;
    END
  END wdata[7]
  PIN wdata[8]
    DIRECTION INPUT ;
    USE SIGNAL ;
    ANTENNAGATEAREA 1.177200 ;
    ANTENNADIFFAREA 0.434700 ;
    PORT
      LAYER met3 ;
        RECT 0.000 649.440 4.000 650.040 ;
    END
  END wdata[8]
  PIN wdata[9]
    DIRECTION INPUT ;
    USE SIGNAL ;
    ANTENNAGATEAREA 0.929700 ;
    ANTENNADIFFAREA 0.434700 ;
    PORT
      LAYER met3 ;
        RECT 0.000 588.240 4.000 588.840 ;
    END
  END wdata[9]
  PIN we
    DIRECTION INPUT ;
    USE SIGNAL ;
    ANTENNAGATEAREA 0.860700 ;
    ANTENNADIFFAREA 0.434700 ;
    PORT
      LAYER met3 ;
        RECT 0.000 635.840 4.000 636.440 ;
    END
  END we
  OBS
      LAYER nwell ;
        RECT 5.330 10.795 2435.430 2440.030 ;
      LAYER li1 ;
        RECT 5.520 10.795 2435.240 2439.925 ;
      LAYER met1 ;
        RECT 4.210 1.400 2435.240 2440.080 ;
      LAYER met2 ;
        RECT 4.230 4.280 2433.770 2440.025 ;
        RECT 4.230 0.155 6.250 4.280 ;
        RECT 7.090 0.155 9.470 4.280 ;
        RECT 10.310 0.155 12.690 4.280 ;
        RECT 13.530 0.155 15.910 4.280 ;
        RECT 16.750 0.155 19.130 4.280 ;
        RECT 19.970 0.155 22.350 4.280 ;
        RECT 23.190 0.155 25.570 4.280 ;
        RECT 26.410 0.155 28.790 4.280 ;
        RECT 29.630 0.155 32.010 4.280 ;
        RECT 32.850 0.155 35.230 4.280 ;
        RECT 36.070 0.155 38.450 4.280 ;
        RECT 39.290 0.155 41.670 4.280 ;
        RECT 42.510 0.155 540.770 4.280 ;
        RECT 541.610 0.155 543.990 4.280 ;
        RECT 544.830 0.155 547.210 4.280 ;
        RECT 548.050 0.155 550.430 4.280 ;
        RECT 551.270 0.155 553.650 4.280 ;
        RECT 554.490 0.155 556.870 4.280 ;
        RECT 557.710 0.155 560.090 4.280 ;
        RECT 560.930 0.155 563.310 4.280 ;
        RECT 564.150 0.155 566.530 4.280 ;
        RECT 567.370 0.155 569.750 4.280 ;
        RECT 570.590 0.155 572.970 4.280 ;
        RECT 573.810 0.155 576.190 4.280 ;
        RECT 577.030 0.155 579.410 4.280 ;
        RECT 580.250 0.155 582.630 4.280 ;
        RECT 583.470 0.155 585.850 4.280 ;
        RECT 586.690 0.155 589.070 4.280 ;
        RECT 589.910 0.155 592.290 4.280 ;
        RECT 593.130 0.155 595.510 4.280 ;
        RECT 596.350 0.155 598.730 4.280 ;
        RECT 599.570 0.155 601.950 4.280 ;
        RECT 602.790 0.155 605.170 4.280 ;
        RECT 606.010 0.155 608.390 4.280 ;
        RECT 609.230 0.155 611.610 4.280 ;
        RECT 612.450 0.155 614.830 4.280 ;
        RECT 615.670 0.155 618.050 4.280 ;
        RECT 618.890 0.155 621.270 4.280 ;
        RECT 622.110 0.155 624.490 4.280 ;
        RECT 625.330 0.155 627.710 4.280 ;
        RECT 628.550 0.155 630.930 4.280 ;
        RECT 631.770 0.155 634.150 4.280 ;
        RECT 634.990 0.155 637.370 4.280 ;
        RECT 638.210 0.155 640.590 4.280 ;
        RECT 641.430 0.155 643.810 4.280 ;
        RECT 644.650 0.155 647.030 4.280 ;
        RECT 647.870 0.155 650.250 4.280 ;
        RECT 651.090 0.155 653.470 4.280 ;
        RECT 654.310 0.155 656.690 4.280 ;
        RECT 657.530 0.155 659.910 4.280 ;
        RECT 660.750 0.155 663.130 4.280 ;
        RECT 663.970 0.155 666.350 4.280 ;
        RECT 667.190 0.155 669.570 4.280 ;
        RECT 670.410 0.155 672.790 4.280 ;
        RECT 673.630 0.155 676.010 4.280 ;
        RECT 676.850 0.155 679.230 4.280 ;
        RECT 680.070 0.155 682.450 4.280 ;
        RECT 683.290 0.155 685.670 4.280 ;
        RECT 686.510 0.155 688.890 4.280 ;
        RECT 689.730 0.155 692.110 4.280 ;
        RECT 692.950 0.155 695.330 4.280 ;
        RECT 696.170 0.155 698.550 4.280 ;
        RECT 699.390 0.155 701.770 4.280 ;
        RECT 702.610 0.155 704.990 4.280 ;
        RECT 705.830 0.155 708.210 4.280 ;
        RECT 709.050 0.155 711.430 4.280 ;
        RECT 712.270 0.155 714.650 4.280 ;
        RECT 715.490 0.155 717.870 4.280 ;
        RECT 718.710 0.155 721.090 4.280 ;
        RECT 721.930 0.155 724.310 4.280 ;
        RECT 725.150 0.155 727.530 4.280 ;
        RECT 728.370 0.155 730.750 4.280 ;
        RECT 731.590 0.155 733.970 4.280 ;
        RECT 734.810 0.155 737.190 4.280 ;
        RECT 738.030 0.155 740.410 4.280 ;
        RECT 741.250 0.155 743.630 4.280 ;
        RECT 744.470 0.155 746.850 4.280 ;
        RECT 747.690 0.155 750.070 4.280 ;
        RECT 750.910 0.155 753.290 4.280 ;
        RECT 754.130 0.155 756.510 4.280 ;
        RECT 757.350 0.155 759.730 4.280 ;
        RECT 760.570 0.155 762.950 4.280 ;
        RECT 763.790 0.155 766.170 4.280 ;
        RECT 767.010 0.155 769.390 4.280 ;
        RECT 770.230 0.155 772.610 4.280 ;
        RECT 773.450 0.155 775.830 4.280 ;
        RECT 776.670 0.155 779.050 4.280 ;
        RECT 779.890 0.155 782.270 4.280 ;
        RECT 783.110 0.155 785.490 4.280 ;
        RECT 786.330 0.155 788.710 4.280 ;
        RECT 789.550 0.155 791.930 4.280 ;
        RECT 792.770 0.155 795.150 4.280 ;
        RECT 795.990 0.155 798.370 4.280 ;
        RECT 799.210 0.155 801.590 4.280 ;
        RECT 802.430 0.155 804.810 4.280 ;
        RECT 805.650 0.155 808.030 4.280 ;
        RECT 808.870 0.155 811.250 4.280 ;
        RECT 812.090 0.155 814.470 4.280 ;
        RECT 815.310 0.155 817.690 4.280 ;
        RECT 818.530 0.155 820.910 4.280 ;
        RECT 821.750 0.155 824.130 4.280 ;
        RECT 824.970 0.155 827.350 4.280 ;
        RECT 828.190 0.155 830.570 4.280 ;
        RECT 831.410 0.155 833.790 4.280 ;
        RECT 834.630 0.155 837.010 4.280 ;
        RECT 837.850 0.155 840.230 4.280 ;
        RECT 841.070 0.155 843.450 4.280 ;
        RECT 844.290 0.155 846.670 4.280 ;
        RECT 847.510 0.155 849.890 4.280 ;
        RECT 850.730 0.155 853.110 4.280 ;
        RECT 853.950 0.155 856.330 4.280 ;
        RECT 857.170 0.155 859.550 4.280 ;
        RECT 860.390 0.155 862.770 4.280 ;
        RECT 863.610 0.155 865.990 4.280 ;
        RECT 866.830 0.155 869.210 4.280 ;
        RECT 870.050 0.155 872.430 4.280 ;
        RECT 873.270 0.155 875.650 4.280 ;
        RECT 876.490 0.155 878.870 4.280 ;
        RECT 879.710 0.155 882.090 4.280 ;
        RECT 882.930 0.155 885.310 4.280 ;
        RECT 886.150 0.155 888.530 4.280 ;
        RECT 889.370 0.155 891.750 4.280 ;
        RECT 892.590 0.155 894.970 4.280 ;
        RECT 895.810 0.155 898.190 4.280 ;
        RECT 899.030 0.155 901.410 4.280 ;
        RECT 902.250 0.155 904.630 4.280 ;
        RECT 905.470 0.155 907.850 4.280 ;
        RECT 908.690 0.155 911.070 4.280 ;
        RECT 911.910 0.155 914.290 4.280 ;
        RECT 915.130 0.155 917.510 4.280 ;
        RECT 918.350 0.155 920.730 4.280 ;
        RECT 921.570 0.155 923.950 4.280 ;
        RECT 924.790 0.155 927.170 4.280 ;
        RECT 928.010 0.155 930.390 4.280 ;
        RECT 931.230 0.155 933.610 4.280 ;
        RECT 934.450 0.155 936.830 4.280 ;
        RECT 937.670 0.155 940.050 4.280 ;
        RECT 940.890 0.155 943.270 4.280 ;
        RECT 944.110 0.155 946.490 4.280 ;
        RECT 947.330 0.155 949.710 4.280 ;
        RECT 950.550 0.155 952.930 4.280 ;
        RECT 953.770 0.155 956.150 4.280 ;
        RECT 956.990 0.155 959.370 4.280 ;
        RECT 960.210 0.155 962.590 4.280 ;
        RECT 963.430 0.155 965.810 4.280 ;
        RECT 966.650 0.155 969.030 4.280 ;
        RECT 969.870 0.155 972.250 4.280 ;
        RECT 973.090 0.155 975.470 4.280 ;
        RECT 976.310 0.155 978.690 4.280 ;
        RECT 979.530 0.155 981.910 4.280 ;
        RECT 982.750 0.155 985.130 4.280 ;
        RECT 985.970 0.155 988.350 4.280 ;
        RECT 989.190 0.155 991.570 4.280 ;
        RECT 992.410 0.155 994.790 4.280 ;
        RECT 995.630 0.155 998.010 4.280 ;
        RECT 998.850 0.155 1001.230 4.280 ;
        RECT 1002.070 0.155 1004.450 4.280 ;
        RECT 1005.290 0.155 1007.670 4.280 ;
        RECT 1008.510 0.155 1010.890 4.280 ;
        RECT 1011.730 0.155 1014.110 4.280 ;
        RECT 1014.950 0.155 1017.330 4.280 ;
        RECT 1018.170 0.155 1020.550 4.280 ;
        RECT 1021.390 0.155 1023.770 4.280 ;
        RECT 1024.610 0.155 1026.990 4.280 ;
        RECT 1027.830 0.155 1030.210 4.280 ;
        RECT 1031.050 0.155 1033.430 4.280 ;
        RECT 1034.270 0.155 1036.650 4.280 ;
        RECT 1037.490 0.155 1039.870 4.280 ;
        RECT 1040.710 0.155 1043.090 4.280 ;
        RECT 1043.930 0.155 1046.310 4.280 ;
        RECT 1047.150 0.155 1049.530 4.280 ;
        RECT 1050.370 0.155 1052.750 4.280 ;
        RECT 1053.590 0.155 1055.970 4.280 ;
        RECT 1056.810 0.155 1059.190 4.280 ;
        RECT 1060.030 0.155 1062.410 4.280 ;
        RECT 1063.250 0.155 1065.630 4.280 ;
        RECT 1066.470 0.155 1068.850 4.280 ;
        RECT 1069.690 0.155 1072.070 4.280 ;
        RECT 1072.910 0.155 1075.290 4.280 ;
        RECT 1076.130 0.155 1078.510 4.280 ;
        RECT 1079.350 0.155 1081.730 4.280 ;
        RECT 1082.570 0.155 1084.950 4.280 ;
        RECT 1085.790 0.155 1088.170 4.280 ;
        RECT 1089.010 0.155 1091.390 4.280 ;
        RECT 1092.230 0.155 1094.610 4.280 ;
        RECT 1095.450 0.155 1097.830 4.280 ;
        RECT 1098.670 0.155 1101.050 4.280 ;
        RECT 1101.890 0.155 1104.270 4.280 ;
        RECT 1105.110 0.155 1107.490 4.280 ;
        RECT 1108.330 0.155 1110.710 4.280 ;
        RECT 1111.550 0.155 1113.930 4.280 ;
        RECT 1114.770 0.155 1117.150 4.280 ;
        RECT 1117.990 0.155 1120.370 4.280 ;
        RECT 1121.210 0.155 1123.590 4.280 ;
        RECT 1124.430 0.155 1126.810 4.280 ;
        RECT 1127.650 0.155 1130.030 4.280 ;
        RECT 1130.870 0.155 1133.250 4.280 ;
        RECT 1134.090 0.155 1136.470 4.280 ;
        RECT 1137.310 0.155 1139.690 4.280 ;
        RECT 1140.530 0.155 1142.910 4.280 ;
        RECT 1143.750 0.155 1146.130 4.280 ;
        RECT 1146.970 0.155 1149.350 4.280 ;
        RECT 1150.190 0.155 1152.570 4.280 ;
        RECT 1153.410 0.155 1155.790 4.280 ;
        RECT 1156.630 0.155 1159.010 4.280 ;
        RECT 1159.850 0.155 1162.230 4.280 ;
        RECT 1163.070 0.155 1165.450 4.280 ;
        RECT 1166.290 0.155 1168.670 4.280 ;
        RECT 1169.510 0.155 1171.890 4.280 ;
        RECT 1172.730 0.155 1175.110 4.280 ;
        RECT 1175.950 0.155 1178.330 4.280 ;
        RECT 1179.170 0.155 1181.550 4.280 ;
        RECT 1182.390 0.155 1184.770 4.280 ;
        RECT 1185.610 0.155 1187.990 4.280 ;
        RECT 1188.830 0.155 1191.210 4.280 ;
        RECT 1192.050 0.155 1194.430 4.280 ;
        RECT 1195.270 0.155 1197.650 4.280 ;
        RECT 1198.490 0.155 1200.870 4.280 ;
        RECT 1201.710 0.155 1204.090 4.280 ;
        RECT 1204.930 0.155 1207.310 4.280 ;
        RECT 1208.150 0.155 1210.530 4.280 ;
        RECT 1211.370 0.155 1213.750 4.280 ;
        RECT 1214.590 0.155 1216.970 4.280 ;
        RECT 1217.810 0.155 1220.190 4.280 ;
        RECT 1221.030 0.155 1223.410 4.280 ;
        RECT 1224.250 0.155 1226.630 4.280 ;
        RECT 1227.470 0.155 1229.850 4.280 ;
        RECT 1230.690 0.155 1233.070 4.280 ;
        RECT 1233.910 0.155 1236.290 4.280 ;
        RECT 1237.130 0.155 1239.510 4.280 ;
        RECT 1240.350 0.155 1242.730 4.280 ;
        RECT 1243.570 0.155 1245.950 4.280 ;
        RECT 1246.790 0.155 1249.170 4.280 ;
        RECT 1250.010 0.155 1252.390 4.280 ;
        RECT 1253.230 0.155 1255.610 4.280 ;
        RECT 1256.450 0.155 1258.830 4.280 ;
        RECT 1259.670 0.155 1262.050 4.280 ;
        RECT 1262.890 0.155 1265.270 4.280 ;
        RECT 1266.110 0.155 1268.490 4.280 ;
        RECT 1269.330 0.155 1271.710 4.280 ;
        RECT 1272.550 0.155 1274.930 4.280 ;
        RECT 1275.770 0.155 1278.150 4.280 ;
        RECT 1278.990 0.155 1281.370 4.280 ;
        RECT 1282.210 0.155 1284.590 4.280 ;
        RECT 1285.430 0.155 1287.810 4.280 ;
        RECT 1288.650 0.155 1291.030 4.280 ;
        RECT 1291.870 0.155 1294.250 4.280 ;
        RECT 1295.090 0.155 1297.470 4.280 ;
        RECT 1298.310 0.155 1300.690 4.280 ;
        RECT 1301.530 0.155 1303.910 4.280 ;
        RECT 1304.750 0.155 1307.130 4.280 ;
        RECT 1307.970 0.155 1310.350 4.280 ;
        RECT 1311.190 0.155 1313.570 4.280 ;
        RECT 1314.410 0.155 1316.790 4.280 ;
        RECT 1317.630 0.155 1320.010 4.280 ;
        RECT 1320.850 0.155 1323.230 4.280 ;
        RECT 1324.070 0.155 1326.450 4.280 ;
        RECT 1327.290 0.155 1329.670 4.280 ;
        RECT 1330.510 0.155 1332.890 4.280 ;
        RECT 1333.730 0.155 1336.110 4.280 ;
        RECT 1336.950 0.155 1339.330 4.280 ;
        RECT 1340.170 0.155 2433.770 4.280 ;
      LAYER met3 ;
        RECT 3.990 732.040 2436.915 2440.005 ;
        RECT 4.400 730.640 2436.915 732.040 ;
        RECT 3.990 728.640 2436.915 730.640 ;
        RECT 4.400 727.240 2436.915 728.640 ;
        RECT 3.990 725.240 2436.915 727.240 ;
        RECT 4.400 723.840 2436.915 725.240 ;
        RECT 3.990 721.840 2436.915 723.840 ;
        RECT 4.400 720.440 2436.915 721.840 ;
        RECT 3.990 718.440 2436.915 720.440 ;
        RECT 4.400 717.040 2436.915 718.440 ;
        RECT 3.990 715.040 2436.915 717.040 ;
        RECT 4.400 713.640 2436.915 715.040 ;
        RECT 3.990 711.640 2436.915 713.640 ;
        RECT 4.400 710.240 2436.915 711.640 ;
        RECT 3.990 708.240 2436.915 710.240 ;
        RECT 4.400 706.840 2436.915 708.240 ;
        RECT 3.990 704.840 2436.915 706.840 ;
        RECT 4.400 703.440 2436.915 704.840 ;
        RECT 3.990 701.440 2436.915 703.440 ;
        RECT 4.400 700.040 2436.915 701.440 ;
        RECT 3.990 698.040 2436.915 700.040 ;
        RECT 4.400 696.640 2436.915 698.040 ;
        RECT 3.990 694.640 2436.915 696.640 ;
        RECT 4.400 693.240 2436.915 694.640 ;
        RECT 3.990 691.240 2436.915 693.240 ;
        RECT 4.400 689.840 2436.915 691.240 ;
        RECT 3.990 687.840 2436.915 689.840 ;
        RECT 4.400 686.440 2436.915 687.840 ;
        RECT 3.990 684.440 2436.915 686.440 ;
        RECT 4.400 683.040 2436.915 684.440 ;
        RECT 3.990 681.040 2436.915 683.040 ;
        RECT 4.400 679.640 2436.515 681.040 ;
        RECT 3.990 677.640 2436.915 679.640 ;
        RECT 4.400 676.240 2436.915 677.640 ;
        RECT 3.990 674.240 2436.915 676.240 ;
        RECT 4.400 672.840 2436.915 674.240 ;
        RECT 3.990 670.840 2436.915 672.840 ;
        RECT 4.400 669.440 2436.915 670.840 ;
        RECT 3.990 667.440 2436.915 669.440 ;
        RECT 4.400 666.040 2436.915 667.440 ;
        RECT 3.990 664.040 2436.915 666.040 ;
        RECT 4.400 662.640 2436.915 664.040 ;
        RECT 3.990 660.640 2436.915 662.640 ;
        RECT 4.400 659.240 2436.915 660.640 ;
        RECT 3.990 657.240 2436.915 659.240 ;
        RECT 4.400 655.840 2436.915 657.240 ;
        RECT 3.990 653.840 2436.915 655.840 ;
        RECT 4.400 652.440 2436.915 653.840 ;
        RECT 3.990 650.440 2436.915 652.440 ;
        RECT 4.400 649.040 2436.915 650.440 ;
        RECT 3.990 647.040 2436.915 649.040 ;
        RECT 4.400 645.640 2436.915 647.040 ;
        RECT 3.990 643.640 2436.915 645.640 ;
        RECT 4.400 642.240 2436.915 643.640 ;
        RECT 3.990 640.240 2436.915 642.240 ;
        RECT 4.400 638.840 2436.915 640.240 ;
        RECT 3.990 636.840 2436.915 638.840 ;
        RECT 4.400 635.440 2436.915 636.840 ;
        RECT 3.990 633.440 2436.915 635.440 ;
        RECT 4.400 632.040 2436.915 633.440 ;
        RECT 3.990 630.040 2436.915 632.040 ;
        RECT 4.400 628.640 2436.915 630.040 ;
        RECT 3.990 626.640 2436.915 628.640 ;
        RECT 4.400 625.240 2436.915 626.640 ;
        RECT 3.990 623.240 2436.915 625.240 ;
        RECT 4.400 621.840 2436.915 623.240 ;
        RECT 3.990 619.840 2436.915 621.840 ;
        RECT 4.400 618.440 2436.915 619.840 ;
        RECT 3.990 616.440 2436.915 618.440 ;
        RECT 4.400 615.040 2436.915 616.440 ;
        RECT 3.990 613.040 2436.915 615.040 ;
        RECT 4.400 611.640 2436.915 613.040 ;
        RECT 3.990 609.640 2436.915 611.640 ;
        RECT 4.400 608.240 2436.915 609.640 ;
        RECT 3.990 606.240 2436.915 608.240 ;
        RECT 4.400 604.840 2436.915 606.240 ;
        RECT 3.990 602.840 2436.915 604.840 ;
        RECT 4.400 601.440 2436.915 602.840 ;
        RECT 3.990 599.440 2436.915 601.440 ;
        RECT 4.400 598.040 2436.915 599.440 ;
        RECT 3.990 596.040 2436.915 598.040 ;
        RECT 4.400 594.640 2436.915 596.040 ;
        RECT 3.990 592.640 2436.915 594.640 ;
        RECT 4.400 591.240 2436.915 592.640 ;
        RECT 3.990 589.240 2436.915 591.240 ;
        RECT 4.400 587.840 2436.915 589.240 ;
        RECT 3.990 585.840 2436.915 587.840 ;
        RECT 4.400 584.440 2436.915 585.840 ;
        RECT 3.990 582.440 2436.915 584.440 ;
        RECT 4.400 581.040 2436.915 582.440 ;
        RECT 3.990 579.040 2436.915 581.040 ;
        RECT 4.400 577.640 2436.915 579.040 ;
        RECT 3.990 575.640 2436.915 577.640 ;
        RECT 4.400 574.240 2436.915 575.640 ;
        RECT 3.990 572.240 2436.915 574.240 ;
        RECT 4.400 570.840 2436.915 572.240 ;
        RECT 3.990 568.840 2436.915 570.840 ;
        RECT 4.400 567.440 2436.915 568.840 ;
        RECT 3.990 565.440 2436.915 567.440 ;
        RECT 4.400 564.040 2436.915 565.440 ;
        RECT 3.990 562.040 2436.915 564.040 ;
        RECT 4.400 560.640 2436.915 562.040 ;
        RECT 3.990 558.640 2436.915 560.640 ;
        RECT 4.400 557.240 2436.915 558.640 ;
        RECT 3.990 555.240 2436.915 557.240 ;
        RECT 4.400 553.840 2436.915 555.240 ;
        RECT 3.990 551.840 2436.915 553.840 ;
        RECT 4.400 550.440 2436.915 551.840 ;
        RECT 3.990 548.440 2436.915 550.440 ;
        RECT 4.400 547.040 2436.915 548.440 ;
        RECT 3.990 545.040 2436.915 547.040 ;
        RECT 4.400 543.640 2436.915 545.040 ;
        RECT 3.990 541.640 2436.915 543.640 ;
        RECT 4.400 540.240 2436.915 541.640 ;
        RECT 3.990 538.240 2436.915 540.240 ;
        RECT 4.400 536.840 2436.915 538.240 ;
        RECT 3.990 534.840 2436.915 536.840 ;
        RECT 4.400 533.440 2436.915 534.840 ;
        RECT 3.990 531.440 2436.915 533.440 ;
        RECT 4.400 530.040 2436.915 531.440 ;
        RECT 3.990 528.040 2436.915 530.040 ;
        RECT 4.400 526.640 2436.915 528.040 ;
        RECT 3.990 524.640 2436.915 526.640 ;
        RECT 4.400 523.240 2436.915 524.640 ;
        RECT 3.990 521.240 2436.915 523.240 ;
        RECT 4.400 519.840 2436.915 521.240 ;
        RECT 3.990 517.840 2436.915 519.840 ;
        RECT 4.400 516.440 2436.915 517.840 ;
        RECT 3.990 514.440 2436.915 516.440 ;
        RECT 4.400 513.040 2436.915 514.440 ;
        RECT 3.990 511.040 2436.915 513.040 ;
        RECT 4.400 509.640 2436.915 511.040 ;
        RECT 3.990 507.640 2436.915 509.640 ;
        RECT 4.400 506.240 2436.915 507.640 ;
        RECT 3.990 504.240 2436.915 506.240 ;
        RECT 4.400 502.840 2436.915 504.240 ;
        RECT 3.990 500.840 2436.915 502.840 ;
        RECT 4.400 499.440 2436.915 500.840 ;
        RECT 3.990 497.440 2436.915 499.440 ;
        RECT 4.400 496.040 2436.915 497.440 ;
        RECT 3.990 494.040 2436.915 496.040 ;
        RECT 4.400 492.640 2436.915 494.040 ;
        RECT 3.990 490.640 2436.915 492.640 ;
        RECT 4.400 489.240 2436.915 490.640 ;
        RECT 3.990 487.240 2436.915 489.240 ;
        RECT 4.400 485.840 2436.915 487.240 ;
        RECT 3.990 483.840 2436.915 485.840 ;
        RECT 4.400 482.440 2436.915 483.840 ;
        RECT 3.990 480.440 2436.915 482.440 ;
        RECT 4.400 479.040 2436.915 480.440 ;
        RECT 3.990 477.040 2436.915 479.040 ;
        RECT 4.400 475.640 2436.915 477.040 ;
        RECT 3.990 473.640 2436.915 475.640 ;
        RECT 4.400 472.240 2436.915 473.640 ;
        RECT 3.990 470.240 2436.915 472.240 ;
        RECT 4.400 468.840 2436.915 470.240 ;
        RECT 3.990 466.840 2436.915 468.840 ;
        RECT 4.400 465.440 2436.915 466.840 ;
        RECT 3.990 463.440 2436.915 465.440 ;
        RECT 4.400 462.040 2436.915 463.440 ;
        RECT 3.990 460.040 2436.915 462.040 ;
        RECT 4.400 458.640 2436.915 460.040 ;
        RECT 3.990 456.640 2436.915 458.640 ;
        RECT 4.400 455.240 2436.915 456.640 ;
        RECT 3.990 453.240 2436.915 455.240 ;
        RECT 4.400 451.840 2436.915 453.240 ;
        RECT 3.990 449.840 2436.915 451.840 ;
        RECT 4.400 448.440 2436.915 449.840 ;
        RECT 3.990 446.440 2436.915 448.440 ;
        RECT 4.400 445.040 2436.915 446.440 ;
        RECT 3.990 443.040 2436.915 445.040 ;
        RECT 4.400 441.640 2436.915 443.040 ;
        RECT 3.990 439.640 2436.915 441.640 ;
        RECT 4.400 438.240 2436.915 439.640 ;
        RECT 3.990 436.240 2436.915 438.240 ;
        RECT 4.400 434.840 2436.915 436.240 ;
        RECT 3.990 432.840 2436.915 434.840 ;
        RECT 4.400 431.440 2436.915 432.840 ;
        RECT 3.990 429.440 2436.915 431.440 ;
        RECT 4.400 428.040 2436.915 429.440 ;
        RECT 3.990 426.040 2436.915 428.040 ;
        RECT 4.400 424.640 2436.915 426.040 ;
        RECT 3.990 422.640 2436.915 424.640 ;
        RECT 4.400 421.240 2436.915 422.640 ;
        RECT 3.990 0.175 2436.915 421.240 ;
      LAYER met4 ;
        RECT 11.335 10.240 20.640 2419.265 ;
        RECT 23.040 10.240 23.940 2419.265 ;
        RECT 26.340 10.240 174.240 2419.265 ;
        RECT 176.640 10.240 177.540 2419.265 ;
        RECT 179.940 10.240 327.840 2419.265 ;
        RECT 330.240 10.240 331.140 2419.265 ;
        RECT 333.540 10.240 481.440 2419.265 ;
        RECT 483.840 10.240 484.740 2419.265 ;
        RECT 487.140 10.240 635.040 2419.265 ;
        RECT 637.440 10.240 638.340 2419.265 ;
        RECT 640.740 10.240 788.640 2419.265 ;
        RECT 791.040 10.240 791.940 2419.265 ;
        RECT 794.340 10.240 942.240 2419.265 ;
        RECT 944.640 10.240 945.540 2419.265 ;
        RECT 947.940 10.240 1095.840 2419.265 ;
        RECT 1098.240 10.240 1099.140 2419.265 ;
        RECT 1101.540 10.240 1249.440 2419.265 ;
        RECT 1251.840 10.240 1252.740 2419.265 ;
        RECT 1255.140 10.240 1403.040 2419.265 ;
        RECT 1405.440 10.240 1406.340 2419.265 ;
        RECT 1408.740 10.240 1556.640 2419.265 ;
        RECT 1559.040 10.240 1559.940 2419.265 ;
        RECT 1562.340 10.240 1710.240 2419.265 ;
        RECT 1712.640 10.240 1713.540 2419.265 ;
        RECT 1715.940 10.240 1863.840 2419.265 ;
        RECT 1866.240 10.240 1867.140 2419.265 ;
        RECT 1869.540 10.240 2017.440 2419.265 ;
        RECT 2019.840 10.240 2020.740 2419.265 ;
        RECT 2023.140 10.240 2171.040 2419.265 ;
        RECT 2173.440 10.240 2174.340 2419.265 ;
        RECT 2176.740 10.240 2324.640 2419.265 ;
        RECT 2327.040 10.240 2327.940 2419.265 ;
        RECT 2330.340 10.240 2426.665 2419.265 ;
        RECT 11.335 0.175 2426.665 10.240 ;
      LAYER met5 ;
        RECT 423.780 1718.210 2315.980 1756.900 ;
        RECT 423.780 1565.030 2315.980 1710.110 ;
        RECT 423.780 1411.850 2315.980 1556.930 ;
        RECT 423.780 1258.670 2315.980 1403.750 ;
        RECT 423.780 1105.490 2315.980 1250.570 ;
        RECT 423.780 952.310 2315.980 1097.390 ;
        RECT 423.780 799.130 2315.980 944.210 ;
        RECT 423.780 645.950 2315.980 791.030 ;
        RECT 423.780 492.770 2315.980 637.850 ;
        RECT 423.780 339.590 2315.980 484.670 ;
        RECT 423.780 186.410 2315.980 331.490 ;
        RECT 423.780 33.230 2315.980 178.310 ;
        RECT 423.780 14.500 2315.980 25.130 ;
  END
END matmul_accel
END LIBRARY

